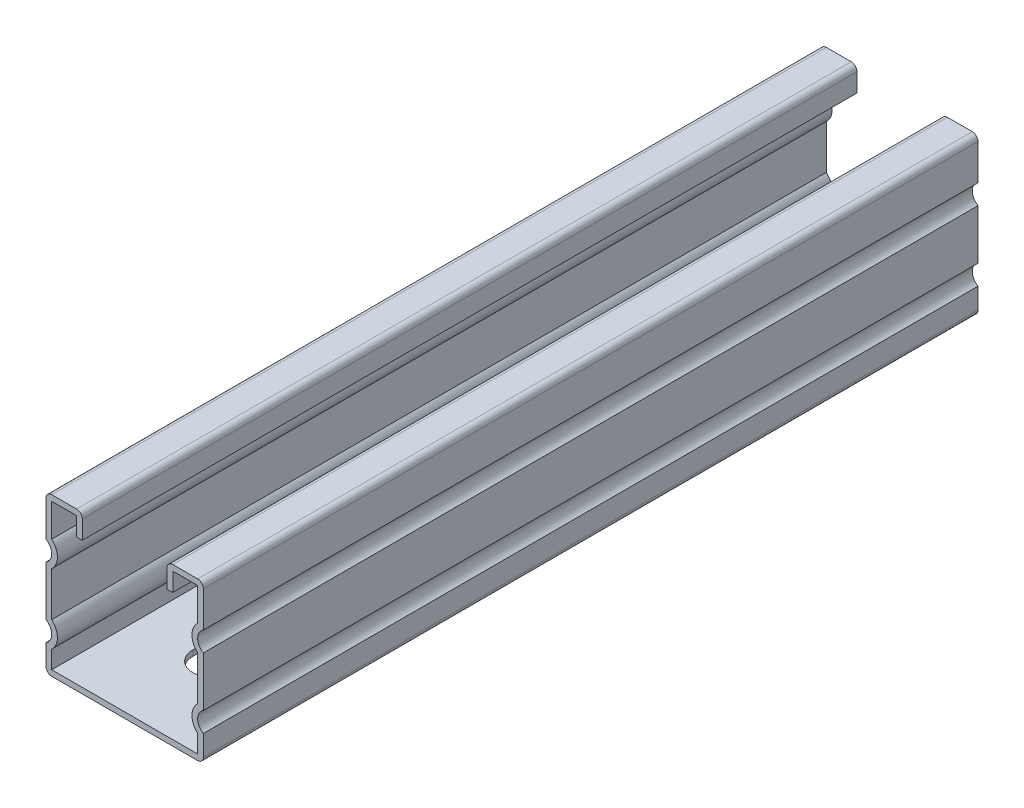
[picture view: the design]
ISO-10303-21;
HEADER;
FILE_DESCRIPTION(('STEP AP214'),'2;1');
FILE_NAME('part.step','',(''),(''),'','','');
FILE_SCHEMA(('AUTOMOTIVE_DESIGN { 1 0 10303 214 1 1 1 1 }'));
ENDSEC;
DATA;
#1=APPLICATION_CONTEXT('core data for automotive mechanical design processes');
#2=APPLICATION_PROTOCOL_DEFINITION('international standard','automotive_design',2000,#1);
#3=PRODUCT_CONTEXT('',#1,'mechanical');
#4=PRODUCT('Part','Part','',(#3));
#5=PRODUCT_RELATED_PRODUCT_CATEGORY('part','',(#4));
#6=PRODUCT_DEFINITION_FORMATION('','',#4);
#7=PRODUCT_DEFINITION_CONTEXT('part definition',#1,'design');
#8=PRODUCT_DEFINITION('design','',#6,#7);
#9=PRODUCT_DEFINITION_SHAPE('','',#8);
#10=(LENGTH_UNIT() NAMED_UNIT(*) SI_UNIT(.MILLI.,.METRE.));
#11=(NAMED_UNIT(*) PLANE_ANGLE_UNIT() SI_UNIT($,.RADIAN.));
#12=(NAMED_UNIT(*) SI_UNIT($,.STERADIAN.) SOLID_ANGLE_UNIT());
#13=UNCERTAINTY_MEASURE_WITH_UNIT(LENGTH_MEASURE(1.E-05),#10,'distance_accuracy_value','');
#14=(GEOMETRIC_REPRESENTATION_CONTEXT(3) GLOBAL_UNCERTAINTY_ASSIGNED_CONTEXT((#13)) GLOBAL_UNIT_ASSIGNED_CONTEXT((#10,
#11,#12)) REPRESENTATION_CONTEXT('',''));
#15=CARTESIAN_POINT('',(0.,0.,0.));
#16=DIRECTION('',(0.,0.,1.));
#17=DIRECTION('',(1.,0.,0.));
#18=AXIS2_PLACEMENT_3D('',#15,#16,#17);
#19=CARTESIAN_POINT('',(-19.1389,21.1074,203.2));
#20=DIRECTION('',(-1.,0.,0.));
#21=DIRECTION('',(0.,-1.,0.));
#22=AXIS2_PLACEMENT_3D('',#19,#20,#21);
#23=PLANE('',#22);
#24=DIRECTION('',(0.,1.,0.));
#25=VECTOR('',#24,1.);
#26=CARTESIAN_POINT('',(-19.1389,21.1074,0.));
#27=LINE('',#26,#25);
#28=CARTESIAN_POINT('',(-19.1389,12.4949714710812,0.));
#29=VERTEX_POINT('',#28);
#30=CARTESIAN_POINT('',(-19.1389,21.1074,0.));
#31=VERTEX_POINT('',#30);
#32=EDGE_CURVE('E374',#29,#31,#27,.T.);
#33=ORIENTED_EDGE('',*,*,#32,.T.);
#34=DIRECTION('',(0.,0.,-1.));
#35=VECTOR('',#34,1.);
#36=CARTESIAN_POINT('',(-19.1389,21.1074,203.2));
#37=LINE('',#36,#35);
#38=CARTESIAN_POINT('',(-19.1389,21.1074,203.2));
#39=VERTEX_POINT('',#38);
#40=EDGE_CURVE('E645',#39,#31,#37,.T.);
#41=ORIENTED_EDGE('',*,*,#40,.F.);
#42=DIRECTION('',(0.,1.,0.));
#43=VECTOR('',#42,1.);
#44=CARTESIAN_POINT('',(-19.1389,21.1074,203.2));
#45=LINE('',#44,#43);
#46=CARTESIAN_POINT('',(-19.1389,12.4949714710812,203.2));
#47=VERTEX_POINT('',#46);
#48=EDGE_CURVE('E381',#47,#39,#45,.T.);
#49=ORIENTED_EDGE('',*,*,#48,.F.);
#50=DIRECTION('',(0.,0.,-1.));
#51=VECTOR('',#50,1.);
#52=CARTESIAN_POINT('',(-19.1389,12.4949714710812,203.2));
#53=LINE('',#52,#51);
#54=EDGE_CURVE('E459',#47,#29,#53,.T.);
#55=ORIENTED_EDGE('',*,*,#54,.T.);
#56=EDGE_LOOP('',(#33,#41,#49,#55));
#57=FACE_BOUND('',#56,.T.);
#58=ADVANCED_FACE('F33',(#57),#23,.F.);
#59=CARTESIAN_POINT('',(-19.1389,21.1074,203.2));
#60=DIRECTION('',(0.,1.,0.));
#61=DIRECTION('',(-1.,0.,0.));
#62=AXIS2_PLACEMENT_3D('',#59,#60,#61);
#63=PLANE('',#62);
#64=DIRECTION('',(1.,0.,0.));
#65=VECTOR('',#64,1.);
#66=CARTESIAN_POINT('',(-19.1389,21.1074,0.));
#67=LINE('',#66,#65);
#68=CARTESIAN_POINT('',(-12.6111,21.1074,0.));
#69=VERTEX_POINT('',#68);
#70=EDGE_CURVE('E462',#31,#69,#67,.T.);
#71=ORIENTED_EDGE('',*,*,#70,.T.);
#72=DIRECTION('',(0.,0.,-1.));
#73=VECTOR('',#72,1.);
#74=CARTESIAN_POINT('',(-12.6111,21.1074,203.2));
#75=LINE('',#74,#73);
#76=CARTESIAN_POINT('',(-12.6111,21.1074,203.2));
#77=VERTEX_POINT('',#76);
#78=EDGE_CURVE('E642',#77,#69,#75,.T.);
#79=ORIENTED_EDGE('',*,*,#78,.F.);
#80=DIRECTION('',(1.,0.,0.));
#81=VECTOR('',#80,1.);
#82=CARTESIAN_POINT('',(-19.1389,21.1074,203.2));
#83=LINE('',#82,#81);
#84=EDGE_CURVE('E384',#39,#77,#83,.T.);
#85=ORIENTED_EDGE('',*,*,#84,.F.);
#86=ORIENTED_EDGE('',*,*,#40,.T.);
#87=EDGE_LOOP('',(#71,#79,#85,#86));
#88=FACE_BOUND('',#87,.T.);
#89=ADVANCED_FACE('F686',(#88),#63,.F.);
#90=CARTESIAN_POINT('',(-12.6111,21.1074,203.2));
#91=DIRECTION('',(1.,0.,0.));
#92=DIRECTION('',(0.,0.,-1.));
#93=AXIS2_PLACEMENT_3D('',#90,#91,#92);
#94=PLANE('',#93);
#95=DIRECTION('',(0.,-1.,0.));
#96=VECTOR('',#95,1.);
#97=CARTESIAN_POINT('',(-12.6111,21.1074,0.));
#98=LINE('',#97,#96);
#99=CARTESIAN_POINT('',(-12.6111,16.256,0.));
#100=VERTEX_POINT('',#99);
#101=EDGE_CURVE('E464',#69,#100,#98,.T.);
#102=ORIENTED_EDGE('',*,*,#101,.T.);
#103=DIRECTION('',(0.,0.,-1.));
#104=VECTOR('',#103,1.);
#105=CARTESIAN_POINT('',(-12.6111,16.256,203.2));
#106=LINE('',#105,#104);
#107=CARTESIAN_POINT('',(-12.6111,16.256,203.2));
#108=VERTEX_POINT('',#107);
#109=EDGE_CURVE('E639',#108,#100,#106,.T.);
#110=ORIENTED_EDGE('',*,*,#109,.F.);
#111=DIRECTION('',(0.,-1.,0.));
#112=VECTOR('',#111,1.);
#113=CARTESIAN_POINT('',(-12.6111,21.1074,203.2));
#114=LINE('',#113,#112);
#115=EDGE_CURVE('E387',#77,#108,#114,.T.);
#116=ORIENTED_EDGE('',*,*,#115,.F.);
#117=ORIENTED_EDGE('',*,*,#78,.T.);
#118=EDGE_LOOP('',(#102,#110,#116,#117));
#119=FACE_BOUND('',#118,.T.);
#120=ADVANCED_FACE('F691',(#119),#94,.F.);
#121=CARTESIAN_POINT('',(-12.6111,16.256,203.2));
#122=DIRECTION('',(0.,1.,0.));
#123=DIRECTION('',(0.,0.,1.));
#124=AXIS2_PLACEMENT_3D('',#121,#122,#123);
#125=PLANE('',#124);
#126=DIRECTION('',(1.,0.,0.));
#127=VECTOR('',#126,1.);
#128=CARTESIAN_POINT('',(-12.6111,16.256,0.));
#129=LINE('',#128,#127);
#130=CARTESIAN_POINT('',(-11.1125,16.256,0.));
#131=VERTEX_POINT('',#130);
#132=EDGE_CURVE('E466',#100,#131,#129,.T.);
#133=ORIENTED_EDGE('',*,*,#132,.T.);
#134=DIRECTION('',(0.,0.,-1.));
#135=VECTOR('',#134,1.);
#136=CARTESIAN_POINT('',(-11.1125,16.256,203.2));
#137=LINE('',#136,#135);
#138=CARTESIAN_POINT('',(-11.1125,16.256,203.2));
#139=VERTEX_POINT('',#138);
#140=EDGE_CURVE('E636',#139,#131,#137,.T.);
#141=ORIENTED_EDGE('',*,*,#140,.F.);
#142=DIRECTION('',(1.,0.,0.));
#143=VECTOR('',#142,1.);
#144=CARTESIAN_POINT('',(-12.6111,16.256,203.2));
#145=LINE('',#144,#143);
#146=EDGE_CURVE('E389',#108,#139,#145,.T.);
#147=ORIENTED_EDGE('',*,*,#146,.F.);
#148=ORIENTED_EDGE('',*,*,#109,.T.);
#149=EDGE_LOOP('',(#133,#141,#147,#148));
#150=FACE_BOUND('',#149,.T.);
#151=ADVANCED_FACE('F873',(#150),#125,.F.);
#152=CARTESIAN_POINT('',(-11.1125,21.1074,203.2));
#153=DIRECTION('',(-1.,0.,0.));
#154=DIRECTION('',(0.,-1.,0.));
#155=AXIS2_PLACEMENT_3D('',#152,#153,#154);
#156=PLANE('',#155);
#157=DIRECTION('',(0.,1.,0.));
#158=VECTOR('',#157,1.);
#159=CARTESIAN_POINT('',(-11.1125,21.1074,0.));
#160=LINE('',#159,#158);
#161=CARTESIAN_POINT('',(-11.1125,21.1074,0.));
#162=VERTEX_POINT('',#161);
#163=EDGE_CURVE('E468',#131,#162,#160,.T.);
#164=ORIENTED_EDGE('',*,*,#163,.T.);
#165=DIRECTION('',(0.,0.,-1.));
#166=VECTOR('',#165,1.);
#167=CARTESIAN_POINT('',(-11.1125,21.1074,203.2));
#168=LINE('',#167,#166);
#169=CARTESIAN_POINT('',(-11.1125,21.1074,203.2));
#170=VERTEX_POINT('',#169);
#171=EDGE_CURVE('E633',#170,#162,#168,.T.);
#172=ORIENTED_EDGE('',*,*,#171,.F.);
#173=DIRECTION('',(0.,1.,0.));
#174=VECTOR('',#173,1.);
#175=CARTESIAN_POINT('',(-11.1125,21.1074,203.2));
#176=LINE('',#175,#174);
#177=EDGE_CURVE('E391',#139,#170,#176,.T.);
#178=ORIENTED_EDGE('',*,*,#177,.F.);
#179=ORIENTED_EDGE('',*,*,#140,.T.);
#180=EDGE_LOOP('',(#164,#172,#178,#179));
#181=FACE_BOUND('',#180,.T.);
#182=ADVANCED_FACE('F869',(#181),#156,.F.);
#183=CARTESIAN_POINT('',(-12.6111,21.1074,203.2));
#184=DIRECTION('',(0.,0.,-1.));
#185=DIRECTION('',(-1.,0.,0.));
#186=AXIS2_PLACEMENT_3D('',#183,#184,#185);
#187=CYLINDRICAL_SURFACE('',#186,1.4986);
#188=CARTESIAN_POINT('',(-12.6111,21.1074,0.));
#189=DIRECTION('',(0.,0.,1.));
#190=DIRECTION('',(-1.,0.,0.));
#191=AXIS2_PLACEMENT_3D('',#188,#189,#190);
#192=CIRCLE('',#191,1.4986);
#193=CARTESIAN_POINT('',(-12.6111,22.606,0.));
#194=VERTEX_POINT('',#193);
#195=EDGE_CURVE('E470',#162,#194,#192,.T.);
#196=ORIENTED_EDGE('',*,*,#195,.T.);
#197=DIRECTION('',(0.,0.,-1.));
#198=VECTOR('',#197,1.);
#199=CARTESIAN_POINT('',(-12.6111,22.606,203.2));
#200=LINE('',#199,#198);
#201=CARTESIAN_POINT('',(-12.6111,22.606,203.2));
#202=VERTEX_POINT('',#201);
#203=EDGE_CURVE('E630',#202,#194,#200,.T.);
#204=ORIENTED_EDGE('',*,*,#203,.F.);
#205=CARTESIAN_POINT('',(-12.6111,21.1074,203.2));
#206=DIRECTION('',(0.,0.,1.));
#207=DIRECTION('',(-1.,0.,0.));
#208=AXIS2_PLACEMENT_3D('',#205,#206,#207);
#209=CIRCLE('',#208,1.4986);
#210=EDGE_CURVE('E393',#170,#202,#209,.T.);
#211=ORIENTED_EDGE('',*,*,#210,.F.);
#212=ORIENTED_EDGE('',*,*,#171,.T.);
#213=EDGE_LOOP('',(#196,#204,#211,#212));
#214=FACE_BOUND('',#213,.T.);
#215=ADVANCED_FACE('F864',(#214),#187,.T.);
#216=CARTESIAN_POINT('',(-19.1389,22.606,203.2));
#217=DIRECTION('',(0.,-1.,0.));
#218=DIRECTION('',(1.,0.,0.));
#219=AXIS2_PLACEMENT_3D('',#216,#217,#218);
#220=PLANE('',#219);
#221=DIRECTION('',(-1.,0.,0.));
#222=VECTOR('',#221,1.);
#223=CARTESIAN_POINT('',(-19.1389,22.606,0.));
#224=LINE('',#223,#222);
#225=CARTESIAN_POINT('',(-19.1389,22.606,0.));
#226=VERTEX_POINT('',#225);
#227=EDGE_CURVE('E472',#194,#226,#224,.T.);
#228=ORIENTED_EDGE('',*,*,#227,.T.);
#229=DIRECTION('',(0.,0.,-1.));
#230=VECTOR('',#229,1.);
#231=CARTESIAN_POINT('',(-19.1389,22.606,203.2));
#232=LINE('',#231,#230);
#233=CARTESIAN_POINT('',(-19.1389,22.606,203.2));
#234=VERTEX_POINT('',#233);
#235=EDGE_CURVE('E627',#234,#226,#232,.T.);
#236=ORIENTED_EDGE('',*,*,#235,.F.);
#237=DIRECTION('',(-1.,0.,0.));
#238=VECTOR('',#237,1.);
#239=CARTESIAN_POINT('',(-19.1389,22.606,203.2));
#240=LINE('',#239,#238);
#241=EDGE_CURVE('E395',#202,#234,#240,.T.);
#242=ORIENTED_EDGE('',*,*,#241,.F.);
#243=ORIENTED_EDGE('',*,*,#203,.T.);
#244=EDGE_LOOP('',(#228,#236,#242,#243));
#245=FACE_BOUND('',#244,.T.);
#246=ADVANCED_FACE('F859',(#245),#220,.F.);
#247=CARTESIAN_POINT('',(-19.1389,21.1074,203.2));
#248=DIRECTION('',(0.,0.,-1.));
#249=DIRECTION('',(-1.,0.,0.));
#250=AXIS2_PLACEMENT_3D('',#247,#248,#249);
#251=CYLINDRICAL_SURFACE('',#250,1.49860000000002);
#252=CARTESIAN_POINT('',(-19.1389,21.1074,0.));
#253=DIRECTION('',(0.,0.,1.));
#254=DIRECTION('',(-1.,0.,0.));
#255=AXIS2_PLACEMENT_3D('',#252,#253,#254);
#256=CIRCLE('',#255,1.49860000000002);
#257=CARTESIAN_POINT('',(-20.6375,21.1074,0.));
#258=VERTEX_POINT('',#257);
#259=EDGE_CURVE('E474',#226,#258,#256,.T.);
#260=ORIENTED_EDGE('',*,*,#259,.T.);
#261=DIRECTION('',(0.,0.,-1.));
#262=VECTOR('',#261,1.);
#263=CARTESIAN_POINT('',(-20.6375,21.1074,203.2));
#264=LINE('',#263,#262);
#265=CARTESIAN_POINT('',(-20.6375,21.1074,203.2));
#266=VERTEX_POINT('',#265);
#267=EDGE_CURVE('E624',#266,#258,#264,.T.);
#268=ORIENTED_EDGE('',*,*,#267,.F.);
#269=CARTESIAN_POINT('',(-19.1389,21.1074,203.2));
#270=DIRECTION('',(0.,0.,1.));
#271=DIRECTION('',(-1.,0.,0.));
#272=AXIS2_PLACEMENT_3D('',#269,#270,#271);
#273=CIRCLE('',#272,1.49860000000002);
#274=EDGE_CURVE('E397',#234,#266,#273,.T.);
#275=ORIENTED_EDGE('',*,*,#274,.F.);
#276=ORIENTED_EDGE('',*,*,#235,.T.);
#277=EDGE_LOOP('',(#260,#268,#275,#276));
#278=FACE_BOUND('',#277,.T.);
#279=ADVANCED_FACE('F855',(#278),#251,.T.);
#280=CARTESIAN_POINT('',(-20.6375,21.1074,203.2));
#281=DIRECTION('',(1.,0.,0.));
#282=DIRECTION('',(0.,0.,-1.));
#283=AXIS2_PLACEMENT_3D('',#280,#281,#282);
#284=PLANE('',#283);
#285=DIRECTION('',(0.,-1.,0.));
#286=VECTOR('',#285,1.);
#287=CARTESIAN_POINT('',(-20.6375,21.1074,0.));
#288=LINE('',#287,#286);
#289=CARTESIAN_POINT('',(-20.6375,11.7396513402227,0.));
#290=VERTEX_POINT('',#289);
#291=EDGE_CURVE('E476',#258,#290,#288,.T.);
#292=ORIENTED_EDGE('',*,*,#291,.T.);
#293=DIRECTION('',(0.,0.,-1.));
#294=VECTOR('',#293,1.);
#295=CARTESIAN_POINT('',(-20.6375,11.7396513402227,203.2));
#296=LINE('',#295,#294);
#297=CARTESIAN_POINT('',(-20.6375,11.7396513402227,203.2));
#298=VERTEX_POINT('',#297);
#299=EDGE_CURVE('E621',#298,#290,#296,.T.);
#300=ORIENTED_EDGE('',*,*,#299,.F.);
#301=DIRECTION('',(0.,-1.,0.));
#302=VECTOR('',#301,1.);
#303=CARTESIAN_POINT('',(-20.6375,21.1074,203.2));
#304=LINE('',#303,#302);
#305=EDGE_CURVE('E399',#266,#298,#304,.T.);
#306=ORIENTED_EDGE('',*,*,#305,.F.);
#307=ORIENTED_EDGE('',*,*,#267,.T.);
#308=EDGE_LOOP('',(#292,#300,#306,#307));
#309=FACE_BOUND('',#308,.T.);
#310=ADVANCED_FACE('F850',(#309),#284,.F.);
#311=CARTESIAN_POINT('',(-22.1361,9.144,203.2));
#312=DIRECTION('',(0.,0.,-1.));
#313=DIRECTION('',(-1.,0.,0.));
#314=AXIS2_PLACEMENT_3D('',#311,#312,#313);
#315=CYLINDRICAL_SURFACE('',#314,2.9972);
#316=CARTESIAN_POINT('',(-22.1361,9.144,0.));
#317=DIRECTION('',(0.,0.,-1.));
#318=DIRECTION('',(1.,0.,0.));
#319=AXIS2_PLACEMENT_3D('',#316,#317,#318);
#320=CIRCLE('',#319,2.9972);
#321=CARTESIAN_POINT('',(-20.6375,6.54834865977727,0.));
#322=VERTEX_POINT('',#321);
#323=EDGE_CURVE('E478',#290,#322,#320,.T.);
#324=ORIENTED_EDGE('',*,*,#323,.T.);
#325=DIRECTION('',(0.,0.,-1.));
#326=VECTOR('',#325,1.);
#327=CARTESIAN_POINT('',(-20.6375,6.54834865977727,203.2));
#328=LINE('',#327,#326);
#329=CARTESIAN_POINT('',(-20.6375,6.54834865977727,203.2));
#330=VERTEX_POINT('',#329);
#331=EDGE_CURVE('E618',#330,#322,#328,.T.);
#332=ORIENTED_EDGE('',*,*,#331,.F.);
#333=CARTESIAN_POINT('',(-22.1361,9.144,203.2));
#334=DIRECTION('',(0.,0.,-1.));
#335=DIRECTION('',(1.,0.,0.));
#336=AXIS2_PLACEMENT_3D('',#333,#334,#335);
#337=CIRCLE('',#336,2.9972);
#338=EDGE_CURVE('E401',#298,#330,#337,.T.);
#339=ORIENTED_EDGE('',*,*,#338,.F.);
#340=ORIENTED_EDGE('',*,*,#299,.T.);
#341=EDGE_LOOP('',(#324,#332,#339,#340));
#342=FACE_BOUND('',#341,.T.);
#343=ADVANCED_FACE('F844',(#342),#315,.F.);
#344=CARTESIAN_POINT('',(-20.6375,6.54834865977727,203.2));
#345=DIRECTION('',(1.,0.,0.));
#346=DIRECTION('',(0.,0.,-1.));
#347=AXIS2_PLACEMENT_3D('',#344,#345,#346);
#348=PLANE('',#347);
#349=DIRECTION('',(0.,-1.,0.));
#350=VECTOR('',#349,1.);
#351=CARTESIAN_POINT('',(-20.6375,6.54834865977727,0.));
#352=LINE('',#351,#350);
#353=CARTESIAN_POINT('',(-20.6375,-6.54834865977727,0.));
#354=VERTEX_POINT('',#353);
#355=EDGE_CURVE('E480',#322,#354,#352,.T.);
#356=ORIENTED_EDGE('',*,*,#355,.T.);
#357=DIRECTION('',(0.,0.,-1.));
#358=VECTOR('',#357,1.);
#359=CARTESIAN_POINT('',(-20.6375,-6.54834865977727,203.2));
#360=LINE('',#359,#358);
#361=CARTESIAN_POINT('',(-20.6375,-6.54834865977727,203.2));
#362=VERTEX_POINT('',#361);
#363=EDGE_CURVE('E615',#362,#354,#360,.T.);
#364=ORIENTED_EDGE('',*,*,#363,.F.);
#365=DIRECTION('',(0.,-1.,0.));
#366=VECTOR('',#365,1.);
#367=CARTESIAN_POINT('',(-20.6375,6.54834865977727,203.2));
#368=LINE('',#367,#366);
#369=EDGE_CURVE('E403',#330,#362,#368,.T.);
#370=ORIENTED_EDGE('',*,*,#369,.F.);
#371=ORIENTED_EDGE('',*,*,#331,.T.);
#372=EDGE_LOOP('',(#356,#364,#370,#371));
#373=FACE_BOUND('',#372,.T.);
#374=ADVANCED_FACE('F840',(#373),#348,.F.);
#375=CARTESIAN_POINT('',(-22.1361,-9.144,203.2));
#376=DIRECTION('',(0.,0.,-1.));
#377=DIRECTION('',(-1.,0.,0.));
#378=AXIS2_PLACEMENT_3D('',#375,#376,#377);
#379=CYLINDRICAL_SURFACE('',#378,2.9972);
#380=CARTESIAN_POINT('',(-22.1361,-9.144,0.));
#381=DIRECTION('',(0.,0.,-1.));
#382=DIRECTION('',(-1.,0.,0.));
#383=AXIS2_PLACEMENT_3D('',#380,#381,#382);
#384=CIRCLE('',#383,2.9972);
#385=CARTESIAN_POINT('',(-20.6375,-11.7396513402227,0.));
#386=VERTEX_POINT('',#385);
#387=EDGE_CURVE('E482',#354,#386,#384,.T.);
#388=ORIENTED_EDGE('',*,*,#387,.T.);
#389=DIRECTION('',(0.,0.,-1.));
#390=VECTOR('',#389,1.);
#391=CARTESIAN_POINT('',(-20.6375,-11.7396513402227,203.2));
#392=LINE('',#391,#390);
#393=CARTESIAN_POINT('',(-20.6375,-11.7396513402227,203.2));
#394=VERTEX_POINT('',#393);
#395=EDGE_CURVE('E612',#394,#386,#392,.T.);
#396=ORIENTED_EDGE('',*,*,#395,.F.);
#397=CARTESIAN_POINT('',(-22.1361,-9.144,203.2));
#398=DIRECTION('',(0.,0.,-1.));
#399=DIRECTION('',(-1.,0.,0.));
#400=AXIS2_PLACEMENT_3D('',#397,#398,#399);
#401=CIRCLE('',#400,2.9972);
#402=EDGE_CURVE('E405',#362,#394,#401,.T.);
#403=ORIENTED_EDGE('',*,*,#402,.F.);
#404=ORIENTED_EDGE('',*,*,#363,.T.);
#405=EDGE_LOOP('',(#388,#396,#403,#404));
#406=FACE_BOUND('',#405,.T.);
#407=ADVANCED_FACE('F835',(#406),#379,.F.);
#408=CARTESIAN_POINT('',(-20.6375,-11.7396513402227,203.2));
#409=DIRECTION('',(1.,0.,0.));
#410=DIRECTION('',(0.,1.,0.));
#411=AXIS2_PLACEMENT_3D('',#408,#409,#410);
#412=PLANE('',#411);
#413=DIRECTION('',(0.,-1.,0.));
#414=VECTOR('',#413,1.);
#415=CARTESIAN_POINT('',(-20.6375,-11.7396513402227,0.));
#416=LINE('',#415,#414);
#417=CARTESIAN_POINT('',(-20.6375,-17.1704,0.));
#418=VERTEX_POINT('',#417);
#419=EDGE_CURVE('E484',#386,#418,#416,.T.);
#420=ORIENTED_EDGE('',*,*,#419,.T.);
#421=DIRECTION('',(0.,0.,-1.));
#422=VECTOR('',#421,1.);
#423=CARTESIAN_POINT('',(-20.6375,-17.1704,203.2));
#424=LINE('',#423,#422);
#425=CARTESIAN_POINT('',(-20.6375,-17.1704,203.2));
#426=VERTEX_POINT('',#425);
#427=EDGE_CURVE('E609',#426,#418,#424,.T.);
#428=ORIENTED_EDGE('',*,*,#427,.F.);
#429=DIRECTION('',(0.,-1.,0.));
#430=VECTOR('',#429,1.);
#431=CARTESIAN_POINT('',(-20.6375,-11.7396513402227,203.2));
#432=LINE('',#431,#430);
#433=EDGE_CURVE('E407',#394,#426,#432,.T.);
#434=ORIENTED_EDGE('',*,*,#433,.F.);
#435=ORIENTED_EDGE('',*,*,#395,.T.);
#436=EDGE_LOOP('',(#420,#428,#434,#435));
#437=FACE_BOUND('',#436,.T.);
#438=ADVANCED_FACE('F829',(#437),#412,.F.);
#439=CARTESIAN_POINT('',(-19.1389,-17.1704,203.2));
#440=DIRECTION('',(0.,0.,-1.));
#441=DIRECTION('',(-1.,0.,0.));
#442=AXIS2_PLACEMENT_3D('',#439,#440,#441);
#443=CYLINDRICAL_SURFACE('',#442,1.4986);
#444=CARTESIAN_POINT('',(-19.1389,-17.1704,0.));
#445=DIRECTION('',(0.,0.,1.));
#446=DIRECTION('',(-1.,0.,0.));
#447=AXIS2_PLACEMENT_3D('',#444,#445,#446);
#448=CIRCLE('',#447,1.4986);
#449=CARTESIAN_POINT('',(-19.1389,-18.669,0.));
#450=VERTEX_POINT('',#449);
#451=EDGE_CURVE('E486',#418,#450,#448,.T.);
#452=ORIENTED_EDGE('',*,*,#451,.T.);
#453=DIRECTION('',(0.,0.,-1.));
#454=VECTOR('',#453,1.);
#455=CARTESIAN_POINT('',(-19.1389,-18.669,203.2));
#456=LINE('',#455,#454);
#457=CARTESIAN_POINT('',(-19.1389,-18.669,203.2));
#458=VERTEX_POINT('',#457);
#459=EDGE_CURVE('E606',#458,#450,#456,.T.);
#460=ORIENTED_EDGE('',*,*,#459,.F.);
#461=CARTESIAN_POINT('',(-19.1389,-17.1704,203.2));
#462=DIRECTION('',(0.,0.,1.));
#463=DIRECTION('',(-1.,0.,0.));
#464=AXIS2_PLACEMENT_3D('',#461,#462,#463);
#465=CIRCLE('',#464,1.4986);
#466=EDGE_CURVE('E409',#426,#458,#465,.T.);
#467=ORIENTED_EDGE('',*,*,#466,.F.);
#468=ORIENTED_EDGE('',*,*,#427,.T.);
#469=EDGE_LOOP('',(#452,#460,#467,#468));
#470=FACE_BOUND('',#469,.T.);
#471=ADVANCED_FACE('F825',(#470),#443,.T.);
#472=CARTESIAN_POINT('',(-19.1389,-18.669,203.2));
#473=DIRECTION('',(0.,1.,0.));
#474=DIRECTION('',(0.,0.,1.));
#475=AXIS2_PLACEMENT_3D('',#472,#473,#474);
#476=PLANE('',#475);
#477=DIRECTION('',(0.,0.,-1.));
#478=VECTOR('',#477,1.);
#479=CARTESIAN_POINT('',(-5.159375,-18.6689999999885,114.3));
#480=LINE('',#479,#478);
#481=CARTESIAN_POINT('',(-5.15937500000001,-18.669,180.18125));
#482=VERTEX_POINT('',#481);
#483=CARTESIAN_POINT('',(-5.159375,-18.6689999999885,114.3));
#484=VERTEX_POINT('',#483);
#485=EDGE_CURVE('E327',#482,#484,#480,.T.);
#486=ORIENTED_EDGE('',*,*,#485,.F.);
#487=CARTESIAN_POINT('',(0.,-18.6689999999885,180.18125));
#488=DIRECTION('',(0.,-1.,0.));
#489=DIRECTION('',(0.,0.,-1.));
#490=AXIS2_PLACEMENT_3D('',#487,#488,#489);
#491=CIRCLE('',#490,5.159375);
#492=CARTESIAN_POINT('',(5.159375,-18.6689999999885,180.18125));
#493=VERTEX_POINT('',#492);
#494=EDGE_CURVE('E47',#493,#482,#491,.T.);
#495=ORIENTED_EDGE('',*,*,#494,.F.);
#496=DIRECTION('',(0.,0.,1.));
#497=VECTOR('',#496,1.);
#498=CARTESIAN_POINT('',(5.159375,-18.6689999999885,180.18125));
#499=LINE('',#498,#497);
#500=CARTESIAN_POINT('',(5.159375,-18.6689999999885,114.3));
#501=VERTEX_POINT('',#500);
#502=EDGE_CURVE('E343',#501,#493,#499,.T.);
#503=ORIENTED_EDGE('',*,*,#502,.F.);
#504=CARTESIAN_POINT('',(0.,-18.6689999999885,114.3));
#505=DIRECTION('',(0.,-1.,0.));
#506=DIRECTION('',(0.,0.,-1.));
#507=AXIS2_PLACEMENT_3D('',#504,#505,#506);
#508=CIRCLE('',#507,5.159375);
#509=EDGE_CURVE('E337',#484,#501,#508,.T.);
#510=ORIENTED_EDGE('',*,*,#509,.F.);
#511=EDGE_LOOP('',(#486,#495,#503,#510));
#512=FACE_BOUND('',#511,.T.);
#513=DIRECTION('',(0.,0.,-1.));
#514=VECTOR('',#513,1.);
#515=CARTESIAN_POINT('',(-5.159375,-18.6689999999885,12.7));
#516=LINE('',#515,#514);
#517=CARTESIAN_POINT('',(-5.15937500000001,-18.669,78.58125));
#518=VERTEX_POINT('',#517);
#519=CARTESIAN_POINT('',(-5.159375,-18.6689999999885,12.7));
#520=VERTEX_POINT('',#519);
#521=EDGE_CURVE('E362',#518,#520,#516,.T.);
#522=ORIENTED_EDGE('',*,*,#521,.F.);
#523=CARTESIAN_POINT('',(0.,-18.6689999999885,78.58125));
#524=DIRECTION('',(0.,-1.,0.));
#525=DIRECTION('',(0.,0.,-1.));
#526=AXIS2_PLACEMENT_3D('',#523,#524,#525);
#527=CIRCLE('',#526,5.159375);
#528=CARTESIAN_POINT('',(5.159375,-18.6689999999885,78.58125));
#529=VERTEX_POINT('',#528);
#530=EDGE_CURVE('E360',#529,#518,#527,.T.);
#531=ORIENTED_EDGE('',*,*,#530,.F.);
#532=DIRECTION('',(0.,0.,1.));
#533=VECTOR('',#532,1.);
#534=CARTESIAN_POINT('',(5.159375,-18.6689999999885,78.58125));
#535=LINE('',#534,#533);
#536=CARTESIAN_POINT('',(5.159375,-18.6689999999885,12.7));
#537=VERTEX_POINT('',#536);
#538=EDGE_CURVE('E368',#537,#529,#535,.T.);
#539=ORIENTED_EDGE('',*,*,#538,.F.);
#540=CARTESIAN_POINT('',(0.,-18.6689999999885,12.7));
#541=DIRECTION('',(0.,-1.,0.));
#542=DIRECTION('',(0.,0.,-1.));
#543=AXIS2_PLACEMENT_3D('',#540,#541,#542);
#544=CIRCLE('',#543,5.159375);
#545=EDGE_CURVE('E365',#520,#537,#544,.T.);
#546=ORIENTED_EDGE('',*,*,#545,.F.);
#547=EDGE_LOOP('',(#522,#531,#539,#546));
#548=FACE_BOUND('',#547,.T.);
#549=DIRECTION('',(1.,0.,0.));
#550=VECTOR('',#549,1.);
#551=CARTESIAN_POINT('',(-19.1389,-18.669,0.));
#552=LINE('',#551,#550);
#553=CARTESIAN_POINT('',(19.1389,-18.669,0.));
#554=VERTEX_POINT('',#553);
#555=EDGE_CURVE('E488',#450,#554,#552,.T.);
#556=ORIENTED_EDGE('',*,*,#555,.T.);
#557=DIRECTION('',(0.,0.,-1.));
#558=VECTOR('',#557,1.);
#559=CARTESIAN_POINT('',(19.1389,-18.669,203.2));
#560=LINE('',#559,#558);
#561=CARTESIAN_POINT('',(19.1389,-18.669,203.2));
#562=VERTEX_POINT('',#561);
#563=EDGE_CURVE('E603',#562,#554,#560,.T.);
#564=ORIENTED_EDGE('',*,*,#563,.F.);
#565=DIRECTION('',(1.,0.,0.));
#566=VECTOR('',#565,1.);
#567=CARTESIAN_POINT('',(-19.1389,-18.669,203.2));
#568=LINE('',#567,#566);
#569=EDGE_CURVE('E411',#458,#562,#568,.T.);
#570=ORIENTED_EDGE('',*,*,#569,.F.);
#571=ORIENTED_EDGE('',*,*,#459,.T.);
#572=EDGE_LOOP('',(#556,#564,#570,#571));
#573=FACE_BOUND('',#572,.T.);
#574=ADVANCED_FACE('F341',(#512,#548,#573),#476,.F.);
#575=CARTESIAN_POINT('',(19.1389,-17.1704,203.2));
#576=DIRECTION('',(0.,0.,-1.));
#577=DIRECTION('',(-1.,0.,0.));
#578=AXIS2_PLACEMENT_3D('',#575,#576,#577);
#579=CYLINDRICAL_SURFACE('',#578,1.4986);
#580=CARTESIAN_POINT('',(19.1389,-17.1704,0.));
#581=DIRECTION('',(0.,0.,1.));
#582=DIRECTION('',(-1.,0.,0.));
#583=AXIS2_PLACEMENT_3D('',#580,#581,#582);
#584=CIRCLE('',#583,1.4986);
#585=CARTESIAN_POINT('',(20.6375,-17.1704,0.));
#586=VERTEX_POINT('',#585);
#587=EDGE_CURVE('E490',#554,#586,#584,.T.);
#588=ORIENTED_EDGE('',*,*,#587,.T.);
#589=DIRECTION('',(0.,0.,-1.));
#590=VECTOR('',#589,1.);
#591=CARTESIAN_POINT('',(20.6375,-17.1704,203.2));
#592=LINE('',#591,#590);
#593=CARTESIAN_POINT('',(20.6375,-17.1704,203.2));
#594=VERTEX_POINT('',#593);
#595=EDGE_CURVE('E600',#594,#586,#592,.T.);
#596=ORIENTED_EDGE('',*,*,#595,.F.);
#597=CARTESIAN_POINT('',(19.1389,-17.1704,203.2));
#598=DIRECTION('',(0.,0.,1.));
#599=DIRECTION('',(-1.,0.,0.));
#600=AXIS2_PLACEMENT_3D('',#597,#598,#599);
#601=CIRCLE('',#600,1.4986);
#602=EDGE_CURVE('E413',#562,#594,#601,.T.);
#603=ORIENTED_EDGE('',*,*,#602,.F.);
#604=ORIENTED_EDGE('',*,*,#563,.T.);
#605=EDGE_LOOP('',(#588,#596,#603,#604));
#606=FACE_BOUND('',#605,.T.);
#607=ADVANCED_FACE('F816',(#606),#579,.T.);
#608=CARTESIAN_POINT('',(20.6375,-17.1704,203.2));
#609=DIRECTION('',(-1.,0.,0.));
#610=DIRECTION('',(0.,-1.,0.));
#611=AXIS2_PLACEMENT_3D('',#608,#609,#610);
#612=PLANE('',#611);
#613=DIRECTION('',(0.,1.,0.));
#614=VECTOR('',#613,1.);
#615=CARTESIAN_POINT('',(20.6375,-17.1704,0.));
#616=LINE('',#615,#614);
#617=CARTESIAN_POINT('',(20.6375,-11.7396513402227,0.));
#618=VERTEX_POINT('',#617);
#619=EDGE_CURVE('E492',#586,#618,#616,.T.);
#620=ORIENTED_EDGE('',*,*,#619,.T.);
#621=DIRECTION('',(0.,0.,-1.));
#622=VECTOR('',#621,1.);
#623=CARTESIAN_POINT('',(20.6375,-11.7396513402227,203.2));
#624=LINE('',#623,#622);
#625=CARTESIAN_POINT('',(20.6375,-11.7396513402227,203.2));
#626=VERTEX_POINT('',#625);
#627=EDGE_CURVE('E597',#626,#618,#624,.T.);
#628=ORIENTED_EDGE('',*,*,#627,.F.);
#629=DIRECTION('',(0.,1.,0.));
#630=VECTOR('',#629,1.);
#631=CARTESIAN_POINT('',(20.6375,-17.1704,203.2));
#632=LINE('',#631,#630);
#633=EDGE_CURVE('E415',#594,#626,#632,.T.);
#634=ORIENTED_EDGE('',*,*,#633,.F.);
#635=ORIENTED_EDGE('',*,*,#595,.T.);
#636=EDGE_LOOP('',(#620,#628,#634,#635));
#637=FACE_BOUND('',#636,.T.);
#638=ADVANCED_FACE('F812',(#637),#612,.F.);
#639=CARTESIAN_POINT('',(22.1361,-9.144,203.2));
#640=DIRECTION('',(0.,0.,-1.));
#641=DIRECTION('',(-1.,0.,0.));
#642=AXIS2_PLACEMENT_3D('',#639,#640,#641);
#643=CYLINDRICAL_SURFACE('',#642,2.9972);
#644=CARTESIAN_POINT('',(22.1361,-9.144,0.));
#645=DIRECTION('',(0.,0.,-1.));
#646=DIRECTION('',(-1.,0.,0.));
#647=AXIS2_PLACEMENT_3D('',#644,#645,#646);
#648=CIRCLE('',#647,2.9972);
#649=CARTESIAN_POINT('',(20.6375,-6.54834865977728,0.));
#650=VERTEX_POINT('',#649);
#651=EDGE_CURVE('E494',#618,#650,#648,.T.);
#652=ORIENTED_EDGE('',*,*,#651,.T.);
#653=DIRECTION('',(0.,0.,-1.));
#654=VECTOR('',#653,1.);
#655=CARTESIAN_POINT('',(20.6375,-6.54834865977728,203.2));
#656=LINE('',#655,#654);
#657=CARTESIAN_POINT('',(20.6375,-6.54834865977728,203.2));
#658=VERTEX_POINT('',#657);
#659=EDGE_CURVE('E594',#658,#650,#656,.T.);
#660=ORIENTED_EDGE('',*,*,#659,.F.);
#661=CARTESIAN_POINT('',(22.1361,-9.144,203.2));
#662=DIRECTION('',(0.,0.,-1.));
#663=DIRECTION('',(-1.,0.,0.));
#664=AXIS2_PLACEMENT_3D('',#661,#662,#663);
#665=CIRCLE('',#664,2.9972);
#666=EDGE_CURVE('E417',#626,#658,#665,.T.);
#667=ORIENTED_EDGE('',*,*,#666,.F.);
#668=ORIENTED_EDGE('',*,*,#627,.T.);
#669=EDGE_LOOP('',(#652,#660,#667,#668));
#670=FACE_BOUND('',#669,.T.);
#671=ADVANCED_FACE('F807',(#670),#643,.F.);
#672=CARTESIAN_POINT('',(20.6375,-6.54834865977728,203.2));
#673=DIRECTION('',(-1.,0.,0.));
#674=DIRECTION('',(0.,0.,1.));
#675=AXIS2_PLACEMENT_3D('',#672,#673,#674);
#676=PLANE('',#675);
#677=DIRECTION('',(0.,1.,0.));
#678=VECTOR('',#677,1.);
#679=CARTESIAN_POINT('',(20.6375,-6.54834865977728,0.));
#680=LINE('',#679,#678);
#681=CARTESIAN_POINT('',(20.6375,6.54834865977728,0.));
#682=VERTEX_POINT('',#681);
#683=EDGE_CURVE('E496',#650,#682,#680,.T.);
#684=ORIENTED_EDGE('',*,*,#683,.T.);
#685=DIRECTION('',(0.,0.,-1.));
#686=VECTOR('',#685,1.);
#687=CARTESIAN_POINT('',(20.6375,6.54834865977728,203.2));
#688=LINE('',#687,#686);
#689=CARTESIAN_POINT('',(20.6375,6.54834865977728,203.2));
#690=VERTEX_POINT('',#689);
#691=EDGE_CURVE('E591',#690,#682,#688,.T.);
#692=ORIENTED_EDGE('',*,*,#691,.F.);
#693=DIRECTION('',(0.,1.,0.));
#694=VECTOR('',#693,1.);
#695=CARTESIAN_POINT('',(20.6375,-6.54834865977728,203.2));
#696=LINE('',#695,#694);
#697=EDGE_CURVE('E419',#658,#690,#696,.T.);
#698=ORIENTED_EDGE('',*,*,#697,.F.);
#699=ORIENTED_EDGE('',*,*,#659,.T.);
#700=EDGE_LOOP('',(#684,#692,#698,#699));
#701=FACE_BOUND('',#700,.T.);
#702=ADVANCED_FACE('F801',(#701),#676,.F.);
#703=CARTESIAN_POINT('',(22.1361,9.144,203.2));
#704=DIRECTION('',(0.,0.,-1.));
#705=DIRECTION('',(-1.,0.,0.));
#706=AXIS2_PLACEMENT_3D('',#703,#704,#705);
#707=CYLINDRICAL_SURFACE('',#706,2.9972);
#708=CARTESIAN_POINT('',(22.1361,9.144,0.));
#709=DIRECTION('',(0.,0.,-1.));
#710=DIRECTION('',(1.,0.,0.));
#711=AXIS2_PLACEMENT_3D('',#708,#709,#710);
#712=CIRCLE('',#711,2.9972);
#713=CARTESIAN_POINT('',(20.6375,11.7396513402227,0.));
#714=VERTEX_POINT('',#713);
#715=EDGE_CURVE('E498',#682,#714,#712,.T.);
#716=ORIENTED_EDGE('',*,*,#715,.T.);
#717=DIRECTION('',(0.,0.,-1.));
#718=VECTOR('',#717,1.);
#719=CARTESIAN_POINT('',(20.6375,11.7396513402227,203.2));
#720=LINE('',#719,#718);
#721=CARTESIAN_POINT('',(20.6375,11.7396513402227,203.2));
#722=VERTEX_POINT('',#721);
#723=EDGE_CURVE('E588',#722,#714,#720,.T.);
#724=ORIENTED_EDGE('',*,*,#723,.F.);
#725=CARTESIAN_POINT('',(22.1361,9.144,203.2));
#726=DIRECTION('',(0.,0.,-1.));
#727=DIRECTION('',(1.,0.,0.));
#728=AXIS2_PLACEMENT_3D('',#725,#726,#727);
#729=CIRCLE('',#728,2.9972);
#730=EDGE_CURVE('E421',#690,#722,#729,.T.);
#731=ORIENTED_EDGE('',*,*,#730,.F.);
#732=ORIENTED_EDGE('',*,*,#691,.T.);
#733=EDGE_LOOP('',(#716,#724,#731,#732));
#734=FACE_BOUND('',#733,.T.);
#735=ADVANCED_FACE('F797',(#734),#707,.F.);
#736=CARTESIAN_POINT('',(20.6375,11.7396513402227,203.2));
#737=DIRECTION('',(-1.,0.,0.));
#738=DIRECTION('',(0.,-1.,0.));
#739=AXIS2_PLACEMENT_3D('',#736,#737,#738);
#740=PLANE('',#739);
#741=DIRECTION('',(0.,1.,0.));
#742=VECTOR('',#741,1.);
#743=CARTESIAN_POINT('',(20.6375,11.7396513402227,0.));
#744=LINE('',#743,#742);
#745=CARTESIAN_POINT('',(20.6375,21.1074,0.));
#746=VERTEX_POINT('',#745);
#747=EDGE_CURVE('E500',#714,#746,#744,.T.);
#748=ORIENTED_EDGE('',*,*,#747,.T.);
#749=DIRECTION('',(0.,0.,-1.));
#750=VECTOR('',#749,1.);
#751=CARTESIAN_POINT('',(20.6375,21.1074,203.2));
#752=LINE('',#751,#750);
#753=CARTESIAN_POINT('',(20.6375,21.1074,203.2));
#754=VERTEX_POINT('',#753);
#755=EDGE_CURVE('E585',#754,#746,#752,.T.);
#756=ORIENTED_EDGE('',*,*,#755,.F.);
#757=DIRECTION('',(0.,1.,0.));
#758=VECTOR('',#757,1.);
#759=CARTESIAN_POINT('',(20.6375,11.7396513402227,203.2));
#760=LINE('',#759,#758);
#761=EDGE_CURVE('E423',#722,#754,#760,.T.);
#762=ORIENTED_EDGE('',*,*,#761,.F.);
#763=ORIENTED_EDGE('',*,*,#723,.T.);
#764=EDGE_LOOP('',(#748,#756,#762,#763));
#765=FACE_BOUND('',#764,.T.);
#766=ADVANCED_FACE('F792',(#765),#740,.F.);
#767=CARTESIAN_POINT('',(19.1389,21.1074,203.2));
#768=DIRECTION('',(0.,0.,-1.));
#769=DIRECTION('',(-1.,0.,0.));
#770=AXIS2_PLACEMENT_3D('',#767,#768,#769);
#771=CYLINDRICAL_SURFACE('',#770,1.4986);
#772=CARTESIAN_POINT('',(19.1389,21.1074,0.));
#773=DIRECTION('',(0.,0.,1.));
#774=DIRECTION('',(-1.,0.,0.));
#775=AXIS2_PLACEMENT_3D('',#772,#773,#774);
#776=CIRCLE('',#775,1.4986);
#777=CARTESIAN_POINT('',(19.1389,22.606,0.));
#778=VERTEX_POINT('',#777);
#779=EDGE_CURVE('E502',#746,#778,#776,.T.);
#780=ORIENTED_EDGE('',*,*,#779,.T.);
#781=DIRECTION('',(0.,0.,-1.));
#782=VECTOR('',#781,1.);
#783=CARTESIAN_POINT('',(19.1389,22.606,203.2));
#784=LINE('',#783,#782);
#785=CARTESIAN_POINT('',(19.1389,22.606,203.2));
#786=VERTEX_POINT('',#785);
#787=EDGE_CURVE('E582',#786,#778,#784,.T.);
#788=ORIENTED_EDGE('',*,*,#787,.F.);
#789=CARTESIAN_POINT('',(19.1389,21.1074,203.2));
#790=DIRECTION('',(0.,0.,1.));
#791=DIRECTION('',(-1.,0.,0.));
#792=AXIS2_PLACEMENT_3D('',#789,#790,#791);
#793=CIRCLE('',#792,1.4986);
#794=EDGE_CURVE('E425',#754,#786,#793,.T.);
#795=ORIENTED_EDGE('',*,*,#794,.F.);
#796=ORIENTED_EDGE('',*,*,#755,.T.);
#797=EDGE_LOOP('',(#780,#788,#795,#796));
#798=FACE_BOUND('',#797,.T.);
#799=ADVANCED_FACE('F786',(#798),#771,.T.);
#800=CARTESIAN_POINT('',(19.1389,22.606,203.2));
#801=DIRECTION('',(0.,-1.,0.));
#802=DIRECTION('',(0.,0.,-1.));
#803=AXIS2_PLACEMENT_3D('',#800,#801,#802);
#804=PLANE('',#803);
#805=DIRECTION('',(-1.,0.,0.));
#806=VECTOR('',#805,1.);
#807=CARTESIAN_POINT('',(19.1389,22.606,0.));
#808=LINE('',#807,#806);
#809=CARTESIAN_POINT('',(12.6111,22.606,0.));
#810=VERTEX_POINT('',#809);
#811=EDGE_CURVE('E504',#778,#810,#808,.T.);
#812=ORIENTED_EDGE('',*,*,#811,.T.);
#813=DIRECTION('',(0.,0.,-1.));
#814=VECTOR('',#813,1.);
#815=CARTESIAN_POINT('',(12.6111,22.606,203.2));
#816=LINE('',#815,#814);
#817=CARTESIAN_POINT('',(12.6111,22.606,203.2));
#818=VERTEX_POINT('',#817);
#819=EDGE_CURVE('E579',#818,#810,#816,.T.);
#820=ORIENTED_EDGE('',*,*,#819,.F.);
#821=DIRECTION('',(-1.,0.,0.));
#822=VECTOR('',#821,1.);
#823=CARTESIAN_POINT('',(19.1389,22.606,203.2));
#824=LINE('',#823,#822);
#825=EDGE_CURVE('E427',#786,#818,#824,.T.);
#826=ORIENTED_EDGE('',*,*,#825,.F.);
#827=ORIENTED_EDGE('',*,*,#787,.T.);
#828=EDGE_LOOP('',(#812,#820,#826,#827));
#829=FACE_BOUND('',#828,.T.);
#830=ADVANCED_FACE('F782',(#829),#804,.F.);
#831=CARTESIAN_POINT('',(12.6111,21.1074,203.2));
#832=DIRECTION('',(0.,0.,-1.));
#833=DIRECTION('',(-1.,0.,0.));
#834=AXIS2_PLACEMENT_3D('',#831,#832,#833);
#835=CYLINDRICAL_SURFACE('',#834,1.4986);
#836=CARTESIAN_POINT('',(12.6111,21.1074,0.));
#837=DIRECTION('',(0.,0.,1.));
#838=DIRECTION('',(-1.,0.,0.));
#839=AXIS2_PLACEMENT_3D('',#836,#837,#838);
#840=CIRCLE('',#839,1.4986);
#841=CARTESIAN_POINT('',(11.1125,21.1074,0.));
#842=VERTEX_POINT('',#841);
#843=EDGE_CURVE('E506',#810,#842,#840,.T.);
#844=ORIENTED_EDGE('',*,*,#843,.T.);
#845=DIRECTION('',(0.,0.,-1.));
#846=VECTOR('',#845,1.);
#847=CARTESIAN_POINT('',(11.1125,21.1074,203.2));
#848=LINE('',#847,#846);
#849=CARTESIAN_POINT('',(11.1125,21.1074,203.2));
#850=VERTEX_POINT('',#849);
#851=EDGE_CURVE('E576',#850,#842,#848,.T.);
#852=ORIENTED_EDGE('',*,*,#851,.F.);
#853=CARTESIAN_POINT('',(12.6111,21.1074,203.2));
#854=DIRECTION('',(0.,0.,1.));
#855=DIRECTION('',(-1.,0.,0.));
#856=AXIS2_PLACEMENT_3D('',#853,#854,#855);
#857=CIRCLE('',#856,1.4986);
#858=EDGE_CURVE('E429',#818,#850,#857,.T.);
#859=ORIENTED_EDGE('',*,*,#858,.F.);
#860=ORIENTED_EDGE('',*,*,#819,.T.);
#861=EDGE_LOOP('',(#844,#852,#859,#860));
#862=FACE_BOUND('',#861,.T.);
#863=ADVANCED_FACE('F777',(#862),#835,.T.);
#864=CARTESIAN_POINT('',(11.1125,21.1074,203.2));
#865=DIRECTION('',(1.,0.,0.));
#866=DIRECTION('',(0.,0.,-1.));
#867=AXIS2_PLACEMENT_3D('',#864,#865,#866);
#868=PLANE('',#867);
#869=DIRECTION('',(0.,-1.,0.));
#870=VECTOR('',#869,1.);
#871=CARTESIAN_POINT('',(11.1125,21.1074,0.));
#872=LINE('',#871,#870);
#873=CARTESIAN_POINT('',(11.1125,16.256,0.));
#874=VERTEX_POINT('',#873);
#875=EDGE_CURVE('E508',#842,#874,#872,.T.);
#876=ORIENTED_EDGE('',*,*,#875,.T.);
#877=DIRECTION('',(0.,0.,-1.));
#878=VECTOR('',#877,1.);
#879=CARTESIAN_POINT('',(11.1125,16.256,203.2));
#880=LINE('',#879,#878);
#881=CARTESIAN_POINT('',(11.1125,16.256,203.2));
#882=VERTEX_POINT('',#881);
#883=EDGE_CURVE('E573',#882,#874,#880,.T.);
#884=ORIENTED_EDGE('',*,*,#883,.F.);
#885=DIRECTION('',(0.,-1.,0.));
#886=VECTOR('',#885,1.);
#887=CARTESIAN_POINT('',(11.1125,21.1074,203.2));
#888=LINE('',#887,#886);
#889=EDGE_CURVE('E431',#850,#882,#888,.T.);
#890=ORIENTED_EDGE('',*,*,#889,.F.);
#891=ORIENTED_EDGE('',*,*,#851,.T.);
#892=EDGE_LOOP('',(#876,#884,#890,#891));
#893=FACE_BOUND('',#892,.T.);
#894=ADVANCED_FACE('F771',(#893),#868,.F.);
#895=CARTESIAN_POINT('',(11.1125,16.256,203.2));
#896=DIRECTION('',(0.,1.,0.));
#897=DIRECTION('',(-1.,0.,0.));
#898=AXIS2_PLACEMENT_3D('',#895,#896,#897);
#899=PLANE('',#898);
#900=DIRECTION('',(1.,0.,0.));
#901=VECTOR('',#900,1.);
#902=CARTESIAN_POINT('',(11.1125,16.256,0.));
#903=LINE('',#902,#901);
#904=CARTESIAN_POINT('',(12.6111,16.256,0.));
#905=VERTEX_POINT('',#904);
#906=EDGE_CURVE('E510',#874,#905,#903,.T.);
#907=ORIENTED_EDGE('',*,*,#906,.T.);
#908=DIRECTION('',(0.,0.,-1.));
#909=VECTOR('',#908,1.);
#910=CARTESIAN_POINT('',(12.6111,16.256,203.2));
#911=LINE('',#910,#909);
#912=CARTESIAN_POINT('',(12.6111,16.256,203.2));
#913=VERTEX_POINT('',#912);
#914=EDGE_CURVE('E570',#913,#905,#911,.T.);
#915=ORIENTED_EDGE('',*,*,#914,.F.);
#916=DIRECTION('',(1.,0.,0.));
#917=VECTOR('',#916,1.);
#918=CARTESIAN_POINT('',(11.1125,16.256,203.2));
#919=LINE('',#918,#917);
#920=EDGE_CURVE('E433',#882,#913,#919,.T.);
#921=ORIENTED_EDGE('',*,*,#920,.F.);
#922=ORIENTED_EDGE('',*,*,#883,.T.);
#923=EDGE_LOOP('',(#907,#915,#921,#922));
#924=FACE_BOUND('',#923,.T.);
#925=ADVANCED_FACE('F767',(#924),#899,.F.);
#926=CARTESIAN_POINT('',(12.6111,21.1074,203.2));
#927=DIRECTION('',(-1.,0.,0.));
#928=DIRECTION('',(0.,0.,1.));
#929=AXIS2_PLACEMENT_3D('',#926,#927,#928);
#930=PLANE('',#929);
#931=DIRECTION('',(0.,1.,0.));
#932=VECTOR('',#931,1.);
#933=CARTESIAN_POINT('',(12.6111,21.1074,0.));
#934=LINE('',#933,#932);
#935=CARTESIAN_POINT('',(12.6111,21.1074,0.));
#936=VERTEX_POINT('',#935);
#937=EDGE_CURVE('E512',#905,#936,#934,.T.);
#938=ORIENTED_EDGE('',*,*,#937,.T.);
#939=DIRECTION('',(0.,0.,-1.));
#940=VECTOR('',#939,1.);
#941=CARTESIAN_POINT('',(12.6111,21.1074,203.2));
#942=LINE('',#941,#940);
#943=CARTESIAN_POINT('',(12.6111,21.1074,203.2));
#944=VERTEX_POINT('',#943);
#945=EDGE_CURVE('E567',#944,#936,#942,.T.);
#946=ORIENTED_EDGE('',*,*,#945,.F.);
#947=DIRECTION('',(0.,1.,0.));
#948=VECTOR('',#947,1.);
#949=CARTESIAN_POINT('',(12.6111,21.1074,203.2));
#950=LINE('',#949,#948);
#951=EDGE_CURVE('E435',#913,#944,#950,.T.);
#952=ORIENTED_EDGE('',*,*,#951,.F.);
#953=ORIENTED_EDGE('',*,*,#914,.T.);
#954=EDGE_LOOP('',(#938,#946,#952,#953));
#955=FACE_BOUND('',#954,.T.);
#956=ADVANCED_FACE('F762',(#955),#930,.F.);
#957=CARTESIAN_POINT('',(19.1389,21.1074,203.2));
#958=DIRECTION('',(0.,1.,0.));
#959=DIRECTION('',(0.,0.,1.));
#960=AXIS2_PLACEMENT_3D('',#957,#958,#959);
#961=PLANE('',#960);
#962=DIRECTION('',(1.,0.,0.));
#963=VECTOR('',#962,1.);
#964=CARTESIAN_POINT('',(19.1389,21.1074,0.));
#965=LINE('',#964,#963);
#966=CARTESIAN_POINT('',(19.1389,21.1074,0.));
#967=VERTEX_POINT('',#966);
#968=EDGE_CURVE('E514',#936,#967,#965,.T.);
#969=ORIENTED_EDGE('',*,*,#968,.T.);
#970=DIRECTION('',(0.,0.,-1.));
#971=VECTOR('',#970,1.);
#972=CARTESIAN_POINT('',(19.1389,21.1074,203.2));
#973=LINE('',#972,#971);
#974=CARTESIAN_POINT('',(19.1389,21.1074,203.2));
#975=VERTEX_POINT('',#974);
#976=EDGE_CURVE('E564',#975,#967,#973,.T.);
#977=ORIENTED_EDGE('',*,*,#976,.F.);
#978=DIRECTION('',(1.,0.,0.));
#979=VECTOR('',#978,1.);
#980=CARTESIAN_POINT('',(19.1389,21.1074,203.2));
#981=LINE('',#980,#979);
#982=EDGE_CURVE('E437',#944,#975,#981,.T.);
#983=ORIENTED_EDGE('',*,*,#982,.F.);
#984=ORIENTED_EDGE('',*,*,#945,.T.);
#985=EDGE_LOOP('',(#969,#977,#983,#984));
#986=FACE_BOUND('',#985,.T.);
#987=ADVANCED_FACE('F756',(#986),#961,.F.);
#988=CARTESIAN_POINT('',(19.1389,12.4949714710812,203.2));
#989=DIRECTION('',(1.,0.,0.));
#990=DIRECTION('',(0.,1.,0.));
#991=AXIS2_PLACEMENT_3D('',#988,#989,#990);
#992=PLANE('',#991);
#993=DIRECTION('',(0.,-1.,0.));
#994=VECTOR('',#993,1.);
#995=CARTESIAN_POINT('',(19.1389,12.4949714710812,0.));
#996=LINE('',#995,#994);
#997=CARTESIAN_POINT('',(19.1389,12.4949714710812,0.));
#998=VERTEX_POINT('',#997);
#999=EDGE_CURVE('E516',#967,#998,#996,.T.);
#1000=ORIENTED_EDGE('',*,*,#999,.T.);
#1001=DIRECTION('',(0.,0.,-1.));
#1002=VECTOR('',#1001,1.);
#1003=CARTESIAN_POINT('',(19.1389,12.4949714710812,203.2));
#1004=LINE('',#1003,#1002);
#1005=CARTESIAN_POINT('',(19.1389,12.4949714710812,203.2));
#1006=VERTEX_POINT('',#1005);
#1007=EDGE_CURVE('E561',#1006,#998,#1004,.T.);
#1008=ORIENTED_EDGE('',*,*,#1007,.F.);
#1009=DIRECTION('',(0.,-1.,0.));
#1010=VECTOR('',#1009,1.);
#1011=CARTESIAN_POINT('',(19.1389,12.4949714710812,203.2));
#1012=LINE('',#1011,#1010);
#1013=EDGE_CURVE('E439',#975,#1006,#1012,.T.);
#1014=ORIENTED_EDGE('',*,*,#1013,.F.);
#1015=ORIENTED_EDGE('',*,*,#976,.T.);
#1016=EDGE_LOOP('',(#1000,#1008,#1014,#1015));
#1017=FACE_BOUND('',#1016,.T.);
#1018=ADVANCED_FACE('F752',(#1017),#992,.F.);
#1019=CARTESIAN_POINT('',(22.1361,9.144,203.2));
#1020=DIRECTION('',(0.,0.,-1.));
#1021=DIRECTION('',(-1.,0.,0.));
#1022=AXIS2_PLACEMENT_3D('',#1019,#1020,#1021);
#1023=CYLINDRICAL_SURFACE('',#1022,4.49580000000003);
#1024=CARTESIAN_POINT('',(22.1361,9.144,0.));
#1025=DIRECTION('',(0.,0.,1.));
#1026=DIRECTION('',(1.,0.,0.));
#1027=AXIS2_PLACEMENT_3D('',#1024,#1025,#1026);
#1028=CIRCLE('',#1027,4.49580000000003);
#1029=CARTESIAN_POINT('',(19.1389,5.79302852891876,0.));
#1030=VERTEX_POINT('',#1029);
#1031=EDGE_CURVE('E518',#998,#1030,#1028,.T.);
#1032=ORIENTED_EDGE('',*,*,#1031,.T.);
#1033=DIRECTION('',(0.,0.,-1.));
#1034=VECTOR('',#1033,1.);
#1035=CARTESIAN_POINT('',(19.1389,5.79302852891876,203.2));
#1036=LINE('',#1035,#1034);
#1037=CARTESIAN_POINT('',(19.1389,5.79302852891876,203.2));
#1038=VERTEX_POINT('',#1037);
#1039=EDGE_CURVE('E558',#1038,#1030,#1036,.T.);
#1040=ORIENTED_EDGE('',*,*,#1039,.F.);
#1041=CARTESIAN_POINT('',(22.1361,9.144,203.2));
#1042=DIRECTION('',(0.,0.,1.));
#1043=DIRECTION('',(1.,0.,0.));
#1044=AXIS2_PLACEMENT_3D('',#1041,#1042,#1043);
#1045=CIRCLE('',#1044,4.49580000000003);
#1046=EDGE_CURVE('E441',#1006,#1038,#1045,.T.);
#1047=ORIENTED_EDGE('',*,*,#1046,.F.);
#1048=ORIENTED_EDGE('',*,*,#1007,.T.);
#1049=EDGE_LOOP('',(#1032,#1040,#1047,#1048));
#1050=FACE_BOUND('',#1049,.T.);
#1051=ADVANCED_FACE('F747',(#1050),#1023,.T.);
#1052=CARTESIAN_POINT('',(19.1389,-5.79302852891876,203.2));
#1053=DIRECTION('',(1.,0.,0.));
#1054=DIRECTION('',(0.,0.,-1.));
#1055=AXIS2_PLACEMENT_3D('',#1052,#1053,#1054);
#1056=PLANE('',#1055);
#1057=DIRECTION('',(0.,-1.,0.));
#1058=VECTOR('',#1057,1.);
#1059=CARTESIAN_POINT('',(19.1389,-5.79302852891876,0.));
#1060=LINE('',#1059,#1058);
#1061=CARTESIAN_POINT('',(19.1389,-5.79302852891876,0.));
#1062=VERTEX_POINT('',#1061);
#1063=EDGE_CURVE('E520',#1030,#1062,#1060,.T.);
#1064=ORIENTED_EDGE('',*,*,#1063,.T.);
#1065=DIRECTION('',(0.,0.,-1.));
#1066=VECTOR('',#1065,1.);
#1067=CARTESIAN_POINT('',(19.1389,-5.79302852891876,203.2));
#1068=LINE('',#1067,#1066);
#1069=CARTESIAN_POINT('',(19.1389,-5.79302852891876,203.2));
#1070=VERTEX_POINT('',#1069);
#1071=EDGE_CURVE('E555',#1070,#1062,#1068,.T.);
#1072=ORIENTED_EDGE('',*,*,#1071,.F.);
#1073=DIRECTION('',(0.,-1.,0.));
#1074=VECTOR('',#1073,1.);
#1075=CARTESIAN_POINT('',(19.1389,-5.79302852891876,203.2));
#1076=LINE('',#1075,#1074);
#1077=EDGE_CURVE('E443',#1038,#1070,#1076,.T.);
#1078=ORIENTED_EDGE('',*,*,#1077,.F.);
#1079=ORIENTED_EDGE('',*,*,#1039,.T.);
#1080=EDGE_LOOP('',(#1064,#1072,#1078,#1079));
#1081=FACE_BOUND('',#1080,.T.);
#1082=ADVANCED_FACE('F741',(#1081),#1056,.F.);
#1083=CARTESIAN_POINT('',(22.1361,-9.144,203.2));
#1084=DIRECTION('',(0.,0.,-1.));
#1085=DIRECTION('',(-1.,0.,0.));
#1086=AXIS2_PLACEMENT_3D('',#1083,#1084,#1085);
#1087=CYLINDRICAL_SURFACE('',#1086,4.49580000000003);
#1088=CARTESIAN_POINT('',(22.1361,-9.144,0.));
#1089=DIRECTION('',(0.,0.,1.));
#1090=DIRECTION('',(-1.,0.,0.));
#1091=AXIS2_PLACEMENT_3D('',#1088,#1089,#1090);
#1092=CIRCLE('',#1091,4.49580000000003);
#1093=CARTESIAN_POINT('',(19.1389,-12.4949714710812,0.));
#1094=VERTEX_POINT('',#1093);
#1095=EDGE_CURVE('E522',#1062,#1094,#1092,.T.);
#1096=ORIENTED_EDGE('',*,*,#1095,.T.);
#1097=DIRECTION('',(0.,0.,-1.));
#1098=VECTOR('',#1097,1.);
#1099=CARTESIAN_POINT('',(19.1389,-12.4949714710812,203.2));
#1100=LINE('',#1099,#1098);
#1101=CARTESIAN_POINT('',(19.1389,-12.4949714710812,203.2));
#1102=VERTEX_POINT('',#1101);
#1103=EDGE_CURVE('E552',#1102,#1094,#1100,.T.);
#1104=ORIENTED_EDGE('',*,*,#1103,.F.);
#1105=CARTESIAN_POINT('',(22.1361,-9.144,203.2));
#1106=DIRECTION('',(0.,0.,1.));
#1107=DIRECTION('',(-1.,0.,0.));
#1108=AXIS2_PLACEMENT_3D('',#1105,#1106,#1107);
#1109=CIRCLE('',#1108,4.49580000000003);
#1110=EDGE_CURVE('E445',#1070,#1102,#1109,.T.);
#1111=ORIENTED_EDGE('',*,*,#1110,.F.);
#1112=ORIENTED_EDGE('',*,*,#1071,.T.);
#1113=EDGE_LOOP('',(#1096,#1104,#1111,#1112));
#1114=FACE_BOUND('',#1113,.T.);
#1115=ADVANCED_FACE('F737',(#1114),#1087,.T.);
#1116=CARTESIAN_POINT('',(19.1389,-17.1704,203.2));
#1117=DIRECTION('',(1.,0.,0.));
#1118=DIRECTION('',(0.,0.,-1.));
#1119=AXIS2_PLACEMENT_3D('',#1116,#1117,#1118);
#1120=PLANE('',#1119);
#1121=DIRECTION('',(0.,-1.,0.));
#1122=VECTOR('',#1121,1.);
#1123=CARTESIAN_POINT('',(19.1389,-17.1704,0.));
#1124=LINE('',#1123,#1122);
#1125=CARTESIAN_POINT('',(19.1389,-17.1704,0.));
#1126=VERTEX_POINT('',#1125);
#1127=EDGE_CURVE('E524',#1094,#1126,#1124,.T.);
#1128=ORIENTED_EDGE('',*,*,#1127,.T.);
#1129=DIRECTION('',(0.,0.,-1.));
#1130=VECTOR('',#1129,1.);
#1131=CARTESIAN_POINT('',(19.1389,-17.1704,203.2));
#1132=LINE('',#1131,#1130);
#1133=CARTESIAN_POINT('',(19.1389,-17.1704,203.2));
#1134=VERTEX_POINT('',#1133);
#1135=EDGE_CURVE('E549',#1134,#1126,#1132,.T.);
#1136=ORIENTED_EDGE('',*,*,#1135,.F.);
#1137=DIRECTION('',(0.,-1.,0.));
#1138=VECTOR('',#1137,1.);
#1139=CARTESIAN_POINT('',(19.1389,-17.1704,203.2));
#1140=LINE('',#1139,#1138);
#1141=EDGE_CURVE('E447',#1102,#1134,#1140,.T.);
#1142=ORIENTED_EDGE('',*,*,#1141,.F.);
#1143=ORIENTED_EDGE('',*,*,#1103,.T.);
#1144=EDGE_LOOP('',(#1128,#1136,#1142,#1143));
#1145=FACE_BOUND('',#1144,.T.);
#1146=ADVANCED_FACE('F732',(#1145),#1120,.F.);
#1147=CARTESIAN_POINT('',(-19.1389,-17.1704,203.2));
#1148=DIRECTION('',(0.,-1.,0.));
#1149=DIRECTION('',(0.,0.,-1.));
#1150=AXIS2_PLACEMENT_3D('',#1147,#1148,#1149);
#1151=PLANE('',#1150);
#1152=DIRECTION('',(0.,0.,1.));
#1153=VECTOR('',#1152,1.);
#1154=CARTESIAN_POINT('',(5.159375,-17.1704,304.8));
#1155=LINE('',#1154,#1153);
#1156=CARTESIAN_POINT('',(5.159375,-17.1704,114.3));
#1157=VERTEX_POINT('',#1156);
#1158=CARTESIAN_POINT('',(5.159375,-17.1704,180.18125));
#1159=VERTEX_POINT('',#1158);
#1160=EDGE_CURVE('E353',#1157,#1159,#1155,.T.);
#1161=ORIENTED_EDGE('',*,*,#1160,.T.);
#1162=CARTESIAN_POINT('',(0.,-17.1704,180.18125));
#1163=DIRECTION('',(0.,-1.,0.));
#1164=DIRECTION('',(0.,0.,-1.));
#1165=AXIS2_PLACEMENT_3D('',#1162,#1163,#1164);
#1166=CIRCLE('',#1165,5.159375);
#1167=CARTESIAN_POINT('',(-5.15937500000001,-17.1704,180.18125));
#1168=VERTEX_POINT('',#1167);
#1169=EDGE_CURVE('E357',#1159,#1168,#1166,.T.);
#1170=ORIENTED_EDGE('',*,*,#1169,.T.);
#1171=DIRECTION('',(0.,0.,-1.));
#1172=VECTOR('',#1171,1.);
#1173=CARTESIAN_POINT('',(-5.15937500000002,-17.1704,304.8));
#1174=LINE('',#1173,#1172);
#1175=CARTESIAN_POINT('',(-5.159375,-17.1704,114.3));
#1176=VERTEX_POINT('',#1175);
#1177=EDGE_CURVE('E334',#1168,#1176,#1174,.T.);
#1178=ORIENTED_EDGE('',*,*,#1177,.T.);
#1179=CARTESIAN_POINT('',(0.,-17.1704,114.3));
#1180=DIRECTION('',(0.,-1.,0.));
#1181=DIRECTION('',(0.,0.,-1.));
#1182=AXIS2_PLACEMENT_3D('',#1179,#1180,#1181);
#1183=CIRCLE('',#1182,5.159375);
#1184=EDGE_CURVE('E55',#1176,#1157,#1183,.T.);
#1185=ORIENTED_EDGE('',*,*,#1184,.T.);
#1186=EDGE_LOOP('',(#1161,#1170,#1178,#1185));
#1187=FACE_BOUND('',#1186,.T.);
#1188=DIRECTION('',(0.,0.,1.));
#1189=VECTOR('',#1188,1.);
#1190=CARTESIAN_POINT('',(5.159375,-17.1704,203.2));
#1191=LINE('',#1190,#1189);
#1192=CARTESIAN_POINT('',(5.159375,-17.1704,12.7));
#1193=VERTEX_POINT('',#1192);
#1194=CARTESIAN_POINT('',(5.159375,-17.1704,78.58125));
#1195=VERTEX_POINT('',#1194);
#1196=EDGE_CURVE('E40',#1193,#1195,#1191,.T.);
#1197=ORIENTED_EDGE('',*,*,#1196,.T.);
#1198=CARTESIAN_POINT('',(0.,-17.1704,78.58125));
#1199=DIRECTION('',(0.,-1.,0.));
#1200=DIRECTION('',(0.,0.,-1.));
#1201=AXIS2_PLACEMENT_3D('',#1198,#1199,#1200);
#1202=CIRCLE('',#1201,5.159375);
#1203=CARTESIAN_POINT('',(-5.15937500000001,-17.1704,78.58125));
#1204=VERTEX_POINT('',#1203);
#1205=EDGE_CURVE('E11',#1195,#1204,#1202,.T.);
#1206=ORIENTED_EDGE('',*,*,#1205,.T.);
#1207=DIRECTION('',(0.,0.,-1.));
#1208=VECTOR('',#1207,1.);
#1209=CARTESIAN_POINT('',(-5.15937500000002,-17.1704,203.2));
#1210=LINE('',#1209,#1208);
#1211=CARTESIAN_POINT('',(-5.159375,-17.1704,12.7));
#1212=VERTEX_POINT('',#1211);
#1213=EDGE_CURVE('E648',#1204,#1212,#1210,.T.);
#1214=ORIENTED_EDGE('',*,*,#1213,.T.);
#1215=CARTESIAN_POINT('',(0.,-17.1704,12.7));
#1216=DIRECTION('',(0.,-1.,0.));
#1217=DIRECTION('',(0.,0.,-1.));
#1218=AXIS2_PLACEMENT_3D('',#1215,#1216,#1217);
#1219=CIRCLE('',#1218,5.159375);
#1220=EDGE_CURVE('E651',#1212,#1193,#1219,.T.);
#1221=ORIENTED_EDGE('',*,*,#1220,.T.);
#1222=EDGE_LOOP('',(#1197,#1206,#1214,#1221));
#1223=FACE_BOUND('',#1222,.T.);
#1224=DIRECTION('',(-1.,0.,0.));
#1225=VECTOR('',#1224,1.);
#1226=CARTESIAN_POINT('',(-19.1389,-17.1704,0.));
#1227=LINE('',#1226,#1225);
#1228=CARTESIAN_POINT('',(-19.1389,-17.1704,0.));
#1229=VERTEX_POINT('',#1228);
#1230=EDGE_CURVE('E526',#1126,#1229,#1227,.T.);
#1231=ORIENTED_EDGE('',*,*,#1230,.T.);
#1232=DIRECTION('',(0.,0.,-1.));
#1233=VECTOR('',#1232,1.);
#1234=CARTESIAN_POINT('',(-19.1389,-17.1704,203.2));
#1235=LINE('',#1234,#1233);
#1236=CARTESIAN_POINT('',(-19.1389,-17.1704,203.2));
#1237=VERTEX_POINT('',#1236);
#1238=EDGE_CURVE('E546',#1237,#1229,#1235,.T.);
#1239=ORIENTED_EDGE('',*,*,#1238,.F.);
#1240=DIRECTION('',(-1.,0.,0.));
#1241=VECTOR('',#1240,1.);
#1242=CARTESIAN_POINT('',(-19.1389,-17.1704,203.2));
#1243=LINE('',#1242,#1241);
#1244=EDGE_CURVE('E449',#1134,#1237,#1243,.T.);
#1245=ORIENTED_EDGE('',*,*,#1244,.F.);
#1246=ORIENTED_EDGE('',*,*,#1135,.T.);
#1247=EDGE_LOOP('',(#1231,#1239,#1245,#1246));
#1248=FACE_BOUND('',#1247,.T.);
#1249=ADVANCED_FACE('F655',(#1187,#1223,#1248),#1151,.F.);
#1250=CARTESIAN_POINT('',(-19.1389,-12.4949714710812,203.2));
#1251=DIRECTION('',(-1.,0.,0.));
#1252=DIRECTION('',(0.,0.,1.));
#1253=AXIS2_PLACEMENT_3D('',#1250,#1251,#1252);
#1254=PLANE('',#1253);
#1255=DIRECTION('',(0.,1.,0.));
#1256=VECTOR('',#1255,1.);
#1257=CARTESIAN_POINT('',(-19.1389,-12.4949714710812,0.));
#1258=LINE('',#1257,#1256);
#1259=CARTESIAN_POINT('',(-19.1389,-12.4949714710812,0.));
#1260=VERTEX_POINT('',#1259);
#1261=EDGE_CURVE('E528',#1229,#1260,#1258,.T.);
#1262=ORIENTED_EDGE('',*,*,#1261,.T.);
#1263=DIRECTION('',(0.,0.,-1.));
#1264=VECTOR('',#1263,1.);
#1265=CARTESIAN_POINT('',(-19.1389,-12.4949714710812,203.2));
#1266=LINE('',#1265,#1264);
#1267=CARTESIAN_POINT('',(-19.1389,-12.4949714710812,203.2));
#1268=VERTEX_POINT('',#1267);
#1269=EDGE_CURVE('E543',#1268,#1260,#1266,.T.);
#1270=ORIENTED_EDGE('',*,*,#1269,.F.);
#1271=DIRECTION('',(0.,1.,0.));
#1272=VECTOR('',#1271,1.);
#1273=CARTESIAN_POINT('',(-19.1389,-12.4949714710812,203.2));
#1274=LINE('',#1273,#1272);
#1275=EDGE_CURVE('E451',#1237,#1268,#1274,.T.);
#1276=ORIENTED_EDGE('',*,*,#1275,.F.);
#1277=ORIENTED_EDGE('',*,*,#1238,.T.);
#1278=EDGE_LOOP('',(#1262,#1270,#1276,#1277));
#1279=FACE_BOUND('',#1278,.T.);
#1280=ADVANCED_FACE('F724',(#1279),#1254,.F.);
#1281=CARTESIAN_POINT('',(-22.1361,-9.144,203.2));
#1282=DIRECTION('',(0.,0.,-1.));
#1283=DIRECTION('',(-1.,0.,0.));
#1284=AXIS2_PLACEMENT_3D('',#1281,#1282,#1283);
#1285=CYLINDRICAL_SURFACE('',#1284,4.49580000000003);
#1286=CARTESIAN_POINT('',(-22.1361,-9.144,0.));
#1287=DIRECTION('',(0.,0.,1.));
#1288=DIRECTION('',(-1.,0.,0.));
#1289=AXIS2_PLACEMENT_3D('',#1286,#1287,#1288);
#1290=CIRCLE('',#1289,4.49580000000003);
#1291=CARTESIAN_POINT('',(-19.1389,-5.79302852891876,0.));
#1292=VERTEX_POINT('',#1291);
#1293=EDGE_CURVE('E530',#1260,#1292,#1290,.T.);
#1294=ORIENTED_EDGE('',*,*,#1293,.T.);
#1295=DIRECTION('',(0.,0.,-1.));
#1296=VECTOR('',#1295,1.);
#1297=CARTESIAN_POINT('',(-19.1389,-5.79302852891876,203.2));
#1298=LINE('',#1297,#1296);
#1299=CARTESIAN_POINT('',(-19.1389,-5.79302852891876,203.2));
#1300=VERTEX_POINT('',#1299);
#1301=EDGE_CURVE('E540',#1300,#1292,#1298,.T.);
#1302=ORIENTED_EDGE('',*,*,#1301,.F.);
#1303=CARTESIAN_POINT('',(-22.1361,-9.144,203.2));
#1304=DIRECTION('',(0.,0.,1.));
#1305=DIRECTION('',(-1.,0.,0.));
#1306=AXIS2_PLACEMENT_3D('',#1303,#1304,#1305);
#1307=CIRCLE('',#1306,4.49580000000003);
#1308=EDGE_CURVE('E453',#1268,#1300,#1307,.T.);
#1309=ORIENTED_EDGE('',*,*,#1308,.F.);
#1310=ORIENTED_EDGE('',*,*,#1269,.T.);
#1311=EDGE_LOOP('',(#1294,#1302,#1309,#1310));
#1312=FACE_BOUND('',#1311,.T.);
#1313=ADVANCED_FACE('F719',(#1312),#1285,.T.);
#1314=CARTESIAN_POINT('',(-19.1389,5.79302852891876,203.2));
#1315=DIRECTION('',(-1.,0.,0.));
#1316=DIRECTION('',(0.,0.,1.));
#1317=AXIS2_PLACEMENT_3D('',#1314,#1315,#1316);
#1318=PLANE('',#1317);
#1319=DIRECTION('',(0.,1.,0.));
#1320=VECTOR('',#1319,1.);
#1321=CARTESIAN_POINT('',(-19.1389,5.79302852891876,0.));
#1322=LINE('',#1321,#1320);
#1323=CARTESIAN_POINT('',(-19.1389,5.79302852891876,0.));
#1324=VERTEX_POINT('',#1323);
#1325=EDGE_CURVE('E532',#1292,#1324,#1322,.T.);
#1326=ORIENTED_EDGE('',*,*,#1325,.T.);
#1327=DIRECTION('',(0.,0.,-1.));
#1328=VECTOR('',#1327,1.);
#1329=CARTESIAN_POINT('',(-19.1389,5.79302852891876,203.2));
#1330=LINE('',#1329,#1328);
#1331=CARTESIAN_POINT('',(-19.1389,5.79302852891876,203.2));
#1332=VERTEX_POINT('',#1331);
#1333=EDGE_CURVE('E537',#1332,#1324,#1330,.T.);
#1334=ORIENTED_EDGE('',*,*,#1333,.F.);
#1335=DIRECTION('',(0.,1.,0.));
#1336=VECTOR('',#1335,1.);
#1337=CARTESIAN_POINT('',(-19.1389,5.79302852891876,203.2));
#1338=LINE('',#1337,#1336);
#1339=EDGE_CURVE('E455',#1300,#1332,#1338,.T.);
#1340=ORIENTED_EDGE('',*,*,#1339,.F.);
#1341=ORIENTED_EDGE('',*,*,#1301,.T.);
#1342=EDGE_LOOP('',(#1326,#1334,#1340,#1341));
#1343=FACE_BOUND('',#1342,.T.);
#1344=ADVANCED_FACE('F713',(#1343),#1318,.F.);
#1345=CARTESIAN_POINT('',(-22.1361,9.144,203.2));
#1346=DIRECTION('',(0.,0.,-1.));
#1347=DIRECTION('',(-1.,0.,0.));
#1348=AXIS2_PLACEMENT_3D('',#1345,#1346,#1347);
#1349=CYLINDRICAL_SURFACE('',#1348,4.49580000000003);
#1350=CARTESIAN_POINT('',(-22.1361,9.144,0.));
#1351=DIRECTION('',(0.,0.,1.));
#1352=DIRECTION('',(1.,0.,0.));
#1353=AXIS2_PLACEMENT_3D('',#1350,#1351,#1352);
#1354=CIRCLE('',#1353,4.49580000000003);
#1355=EDGE_CURVE('E385',#1324,#29,#1354,.T.);
#1356=ORIENTED_EDGE('',*,*,#1355,.T.);
#1357=ORIENTED_EDGE('',*,*,#54,.F.);
#1358=CARTESIAN_POINT('',(-22.1361,9.144,203.2));
#1359=DIRECTION('',(0.,0.,1.));
#1360=DIRECTION('',(1.,0.,0.));
#1361=AXIS2_PLACEMENT_3D('',#1358,#1359,#1360);
#1362=CIRCLE('',#1361,4.49580000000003);
#1363=EDGE_CURVE('E457',#1332,#47,#1362,.T.);
#1364=ORIENTED_EDGE('',*,*,#1363,.F.);
#1365=ORIENTED_EDGE('',*,*,#1333,.T.);
#1366=EDGE_LOOP('',(#1356,#1357,#1364,#1365));
#1367=FACE_BOUND('',#1366,.T.);
#1368=ADVANCED_FACE('F711',(#1367),#1349,.T.);
#1369=CARTESIAN_POINT('',(-22.1361,9.144,203.2));
#1370=DIRECTION('',(0.,0.,1.));
#1371=DIRECTION('',(1.,0.,0.));
#1372=AXIS2_PLACEMENT_3D('',#1369,#1370,#1371);
#1373=PLANE('',#1372);
#1374=ORIENTED_EDGE('',*,*,#48,.T.);
#1375=ORIENTED_EDGE('',*,*,#84,.T.);
#1376=ORIENTED_EDGE('',*,*,#115,.T.);
#1377=ORIENTED_EDGE('',*,*,#146,.T.);
#1378=ORIENTED_EDGE('',*,*,#177,.T.);
#1379=ORIENTED_EDGE('',*,*,#210,.T.);
#1380=ORIENTED_EDGE('',*,*,#241,.T.);
#1381=ORIENTED_EDGE('',*,*,#274,.T.);
#1382=ORIENTED_EDGE('',*,*,#305,.T.);
#1383=ORIENTED_EDGE('',*,*,#338,.T.);
#1384=ORIENTED_EDGE('',*,*,#369,.T.);
#1385=ORIENTED_EDGE('',*,*,#402,.T.);
#1386=ORIENTED_EDGE('',*,*,#433,.T.);
#1387=ORIENTED_EDGE('',*,*,#466,.T.);
#1388=ORIENTED_EDGE('',*,*,#569,.T.);
#1389=ORIENTED_EDGE('',*,*,#602,.T.);
#1390=ORIENTED_EDGE('',*,*,#633,.T.);
#1391=ORIENTED_EDGE('',*,*,#666,.T.);
#1392=ORIENTED_EDGE('',*,*,#697,.T.);
#1393=ORIENTED_EDGE('',*,*,#730,.T.);
#1394=ORIENTED_EDGE('',*,*,#761,.T.);
#1395=ORIENTED_EDGE('',*,*,#794,.T.);
#1396=ORIENTED_EDGE('',*,*,#825,.T.);
#1397=ORIENTED_EDGE('',*,*,#858,.T.);
#1398=ORIENTED_EDGE('',*,*,#889,.T.);
#1399=ORIENTED_EDGE('',*,*,#920,.T.);
#1400=ORIENTED_EDGE('',*,*,#951,.T.);
#1401=ORIENTED_EDGE('',*,*,#982,.T.);
#1402=ORIENTED_EDGE('',*,*,#1013,.T.);
#1403=ORIENTED_EDGE('',*,*,#1046,.T.);
#1404=ORIENTED_EDGE('',*,*,#1077,.T.);
#1405=ORIENTED_EDGE('',*,*,#1110,.T.);
#1406=ORIENTED_EDGE('',*,*,#1141,.T.);
#1407=ORIENTED_EDGE('',*,*,#1244,.T.);
#1408=ORIENTED_EDGE('',*,*,#1275,.T.);
#1409=ORIENTED_EDGE('',*,*,#1308,.T.);
#1410=ORIENTED_EDGE('',*,*,#1339,.T.);
#1411=ORIENTED_EDGE('',*,*,#1363,.T.);
#1412=EDGE_LOOP('',(#1374,#1375,#1376,#1377,#1378,#1379,#1380,#1381,#1382,#1383,#1384,#1385,
#1386,#1387,#1388,#1389,#1390,#1391,#1392,#1393,#1394,#1395,#1396,#1397,#1398,#1399,#1400,#1401,
#1402,#1403,#1404,#1405,#1406,#1407,#1408,#1409,#1410,#1411));
#1413=FACE_BOUND('',#1412,.T.);
#1414=ADVANCED_FACE('F706',(#1413),#1373,.T.);
#1415=CARTESIAN_POINT('',(-22.1361,9.144,0.));
#1416=DIRECTION('',(0.,0.,1.));
#1417=DIRECTION('',(1.,0.,0.));
#1418=AXIS2_PLACEMENT_3D('',#1415,#1416,#1417);
#1419=PLANE('',#1418);
#1420=ORIENTED_EDGE('',*,*,#32,.F.);
#1421=ORIENTED_EDGE('',*,*,#1355,.F.);
#1422=ORIENTED_EDGE('',*,*,#1325,.F.);
#1423=ORIENTED_EDGE('',*,*,#1293,.F.);
#1424=ORIENTED_EDGE('',*,*,#1261,.F.);
#1425=ORIENTED_EDGE('',*,*,#1230,.F.);
#1426=ORIENTED_EDGE('',*,*,#1127,.F.);
#1427=ORIENTED_EDGE('',*,*,#1095,.F.);
#1428=ORIENTED_EDGE('',*,*,#1063,.F.);
#1429=ORIENTED_EDGE('',*,*,#1031,.F.);
#1430=ORIENTED_EDGE('',*,*,#999,.F.);
#1431=ORIENTED_EDGE('',*,*,#968,.F.);
#1432=ORIENTED_EDGE('',*,*,#937,.F.);
#1433=ORIENTED_EDGE('',*,*,#906,.F.);
#1434=ORIENTED_EDGE('',*,*,#875,.F.);
#1435=ORIENTED_EDGE('',*,*,#843,.F.);
#1436=ORIENTED_EDGE('',*,*,#811,.F.);
#1437=ORIENTED_EDGE('',*,*,#779,.F.);
#1438=ORIENTED_EDGE('',*,*,#747,.F.);
#1439=ORIENTED_EDGE('',*,*,#715,.F.);
#1440=ORIENTED_EDGE('',*,*,#683,.F.);
#1441=ORIENTED_EDGE('',*,*,#651,.F.);
#1442=ORIENTED_EDGE('',*,*,#619,.F.);
#1443=ORIENTED_EDGE('',*,*,#587,.F.);
#1444=ORIENTED_EDGE('',*,*,#555,.F.);
#1445=ORIENTED_EDGE('',*,*,#451,.F.);
#1446=ORIENTED_EDGE('',*,*,#419,.F.);
#1447=ORIENTED_EDGE('',*,*,#387,.F.);
#1448=ORIENTED_EDGE('',*,*,#355,.F.);
#1449=ORIENTED_EDGE('',*,*,#323,.F.);
#1450=ORIENTED_EDGE('',*,*,#291,.F.);
#1451=ORIENTED_EDGE('',*,*,#259,.F.);
#1452=ORIENTED_EDGE('',*,*,#227,.F.);
#1453=ORIENTED_EDGE('',*,*,#195,.F.);
#1454=ORIENTED_EDGE('',*,*,#163,.F.);
#1455=ORIENTED_EDGE('',*,*,#132,.F.);
#1456=ORIENTED_EDGE('',*,*,#101,.F.);
#1457=ORIENTED_EDGE('',*,*,#70,.F.);
#1458=EDGE_LOOP('',(#1420,#1421,#1422,#1423,#1424,#1425,#1426,#1427,#1428,#1429,#1430,#1431,
#1432,#1433,#1434,#1435,#1436,#1437,#1438,#1439,#1440,#1441,#1442,#1443,#1444,#1445,#1446,#1447,
#1448,#1449,#1450,#1451,#1452,#1453,#1454,#1455,#1456,#1457));
#1459=FACE_BOUND('',#1458,.T.);
#1460=ADVANCED_FACE('F699',(#1459),#1419,.F.);
#1461=CARTESIAN_POINT('',(0.,22.606,78.58125));
#1462=DIRECTION('',(0.,-1.,0.));
#1463=DIRECTION('',(0.,0.,-1.));
#1464=AXIS2_PLACEMENT_3D('',#1461,#1462,#1463);
#1465=CYLINDRICAL_SURFACE('',#1464,5.159375);
#1466=DIRECTION('',(0.,-1.,0.));
#1467=VECTOR('',#1466,1.);
#1468=CARTESIAN_POINT('',(5.159375,22.606,78.58125));
#1469=LINE('',#1468,#1467);
#1470=EDGE_CURVE('E372',#1195,#529,#1469,.T.);
#1471=ORIENTED_EDGE('',*,*,#1470,.T.);
#1472=ORIENTED_EDGE('',*,*,#530,.T.);
#1473=DIRECTION('',(0.,-1.,0.));
#1474=VECTOR('',#1473,1.);
#1475=CARTESIAN_POINT('',(-5.15937500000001,22.606,78.58125));
#1476=LINE('',#1475,#1474);
#1477=EDGE_CURVE('E371',#1204,#518,#1476,.T.);
#1478=ORIENTED_EDGE('',*,*,#1477,.F.);
#1479=ORIENTED_EDGE('',*,*,#1205,.F.);
#1480=EDGE_LOOP('',(#1471,#1472,#1478,#1479));
#1481=FACE_BOUND('',#1480,.T.);
#1482=ADVANCED_FACE('F671',(#1481),#1465,.F.);
#1483=CARTESIAN_POINT('',(5.159375,22.606,78.58125));
#1484=DIRECTION('',(1.,0.,0.));
#1485=DIRECTION('',(0.,0.,-1.));
#1486=AXIS2_PLACEMENT_3D('',#1483,#1484,#1485);
#1487=PLANE('',#1486);
#1488=DIRECTION('',(0.,-1.,0.));
#1489=VECTOR('',#1488,1.);
#1490=CARTESIAN_POINT('',(5.159375,22.606,12.7));
#1491=LINE('',#1490,#1489);
#1492=EDGE_CURVE('E375',#1193,#537,#1491,.T.);
#1493=ORIENTED_EDGE('',*,*,#1492,.T.);
#1494=ORIENTED_EDGE('',*,*,#538,.T.);
#1495=ORIENTED_EDGE('',*,*,#1470,.F.);
#1496=ORIENTED_EDGE('',*,*,#1196,.F.);
#1497=EDGE_LOOP('',(#1493,#1494,#1495,#1496));
#1498=FACE_BOUND('',#1497,.T.);
#1499=ADVANCED_FACE('F661',(#1498),#1487,.F.);
#1500=CARTESIAN_POINT('',(0.,22.606,12.7));
#1501=DIRECTION('',(0.,-1.,0.));
#1502=DIRECTION('',(0.,0.,-1.));
#1503=AXIS2_PLACEMENT_3D('',#1500,#1501,#1502);
#1504=CYLINDRICAL_SURFACE('',#1503,5.159375);
#1505=DIRECTION('',(0.,-1.,0.));
#1506=VECTOR('',#1505,1.);
#1507=CARTESIAN_POINT('',(-5.159375,22.606,12.7));
#1508=LINE('',#1507,#1506);
#1509=EDGE_CURVE('E377',#1212,#520,#1508,.T.);
#1510=ORIENTED_EDGE('',*,*,#1509,.T.);
#1511=ORIENTED_EDGE('',*,*,#545,.T.);
#1512=ORIENTED_EDGE('',*,*,#1492,.F.);
#1513=ORIENTED_EDGE('',*,*,#1220,.F.);
#1514=EDGE_LOOP('',(#1510,#1511,#1512,#1513));
#1515=FACE_BOUND('',#1514,.T.);
#1516=ADVANCED_FACE('F663',(#1515),#1504,.F.);
#1517=CARTESIAN_POINT('',(-5.159375,22.606,12.7));
#1518=DIRECTION('',(-1.,0.,0.));
#1519=DIRECTION('',(0.,0.,1.));
#1520=AXIS2_PLACEMENT_3D('',#1517,#1518,#1519);
#1521=PLANE('',#1520);
#1522=ORIENTED_EDGE('',*,*,#1477,.T.);
#1523=ORIENTED_EDGE('',*,*,#521,.T.);
#1524=ORIENTED_EDGE('',*,*,#1509,.F.);
#1525=ORIENTED_EDGE('',*,*,#1213,.F.);
#1526=EDGE_LOOP('',(#1522,#1523,#1524,#1525));
#1527=FACE_BOUND('',#1526,.T.);
#1528=ADVANCED_FACE('F673',(#1527),#1521,.F.);
#1529=CARTESIAN_POINT('',(0.,22.606,180.18125));
#1530=DIRECTION('',(0.,-1.,0.));
#1531=DIRECTION('',(0.,0.,-1.));
#1532=AXIS2_PLACEMENT_3D('',#1529,#1530,#1531);
#1533=CYLINDRICAL_SURFACE('',#1532,5.159375);
#1534=DIRECTION('',(0.,-1.,0.));
#1535=VECTOR('',#1534,1.);
#1536=CARTESIAN_POINT('',(5.159375,22.606,180.18125));
#1537=LINE('',#1536,#1535);
#1538=EDGE_CURVE('E351',#1159,#493,#1537,.T.);
#1539=ORIENTED_EDGE('',*,*,#1538,.T.);
#1540=ORIENTED_EDGE('',*,*,#494,.T.);
#1541=DIRECTION('',(0.,-1.,0.));
#1542=VECTOR('',#1541,1.);
#1543=CARTESIAN_POINT('',(-5.15937500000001,22.606,180.18125));
#1544=LINE('',#1543,#1542);
#1545=EDGE_CURVE('E331',#1168,#482,#1544,.T.);
#1546=ORIENTED_EDGE('',*,*,#1545,.F.);
#1547=ORIENTED_EDGE('',*,*,#1169,.F.);
#1548=EDGE_LOOP('',(#1539,#1540,#1546,#1547));
#1549=FACE_BOUND('',#1548,.T.);
#1550=ADVANCED_FACE('F675',(#1549),#1533,.F.);
#1551=CARTESIAN_POINT('',(5.159375,22.606,180.18125));
#1552=DIRECTION('',(1.,0.,0.));
#1553=DIRECTION('',(0.,0.,-1.));
#1554=AXIS2_PLACEMENT_3D('',#1551,#1552,#1553);
#1555=PLANE('',#1554);
#1556=DIRECTION('',(0.,-1.,0.));
#1557=VECTOR('',#1556,1.);
#1558=CARTESIAN_POINT('',(5.159375,22.606,114.3));
#1559=LINE('',#1558,#1557);
#1560=EDGE_CURVE('E344',#1157,#501,#1559,.T.);
#1561=ORIENTED_EDGE('',*,*,#1560,.T.);
#1562=ORIENTED_EDGE('',*,*,#502,.T.);
#1563=ORIENTED_EDGE('',*,*,#1538,.F.);
#1564=ORIENTED_EDGE('',*,*,#1160,.F.);
#1565=EDGE_LOOP('',(#1561,#1562,#1563,#1564));
#1566=FACE_BOUND('',#1565,.T.);
#1567=ADVANCED_FACE('F681',(#1566),#1555,.F.);
#1568=CARTESIAN_POINT('',(0.,22.606,114.3));
#1569=DIRECTION('',(0.,-1.,0.));
#1570=DIRECTION('',(0.,0.,-1.));
#1571=AXIS2_PLACEMENT_3D('',#1568,#1569,#1570);
#1572=CYLINDRICAL_SURFACE('',#1571,5.159375);
#1573=DIRECTION('',(0.,-1.,0.));
#1574=VECTOR('',#1573,1.);
#1575=CARTESIAN_POINT('',(-5.159375,22.606,114.3));
#1576=LINE('',#1575,#1574);
#1577=EDGE_CURVE('E329',#1176,#484,#1576,.T.);
#1578=ORIENTED_EDGE('',*,*,#1577,.T.);
#1579=ORIENTED_EDGE('',*,*,#509,.T.);
#1580=ORIENTED_EDGE('',*,*,#1560,.F.);
#1581=ORIENTED_EDGE('',*,*,#1184,.F.);
#1582=EDGE_LOOP('',(#1578,#1579,#1580,#1581));
#1583=FACE_BOUND('',#1582,.T.);
#1584=ADVANCED_FACE('F336',(#1583),#1572,.F.);
#1585=CARTESIAN_POINT('',(-5.159375,22.606,114.3));
#1586=DIRECTION('',(-1.,0.,0.));
#1587=DIRECTION('',(0.,0.,1.));
#1588=AXIS2_PLACEMENT_3D('',#1585,#1586,#1587);
#1589=PLANE('',#1588);
#1590=ORIENTED_EDGE('',*,*,#1545,.T.);
#1591=ORIENTED_EDGE('',*,*,#485,.T.);
#1592=ORIENTED_EDGE('',*,*,#1577,.F.);
#1593=ORIENTED_EDGE('',*,*,#1177,.F.);
#1594=EDGE_LOOP('',(#1590,#1591,#1592,#1593));
#1595=FACE_BOUND('',#1594,.T.);
#1596=ADVANCED_FACE('F328',(#1595),#1589,.F.);
#1597=CLOSED_SHELL('',(#58,#89,#120,#151,#182,#215,#246,#279,#310,#343,#374,#407,#438,#471,#574,
#607,#638,#671,#702,#735,#766,#799,#830,#863,#894,#925,#956,#987,#1018,#1051,#1082,#1115,#1146,
#1249,#1280,#1313,#1344,#1368,#1414,#1460,#1482,#1499,#1516,#1528,#1550,#1567,#1584,#1596));
#1598=MANIFOLD_SOLID_BREP('B2',#1597);
#1599=ADVANCED_BREP_SHAPE_REPRESENTATION('',(#18,#1598),#14);
#1600=SHAPE_DEFINITION_REPRESENTATION(#9,#1599);
ENDSEC;
END-ISO-10303-21;
